VERSION 5.7 ;
  NOWIREEXTENSIONATPIN ON ;
  DIVIDERCHAR "/" ;
  BUSBITCHARS "[]" ;
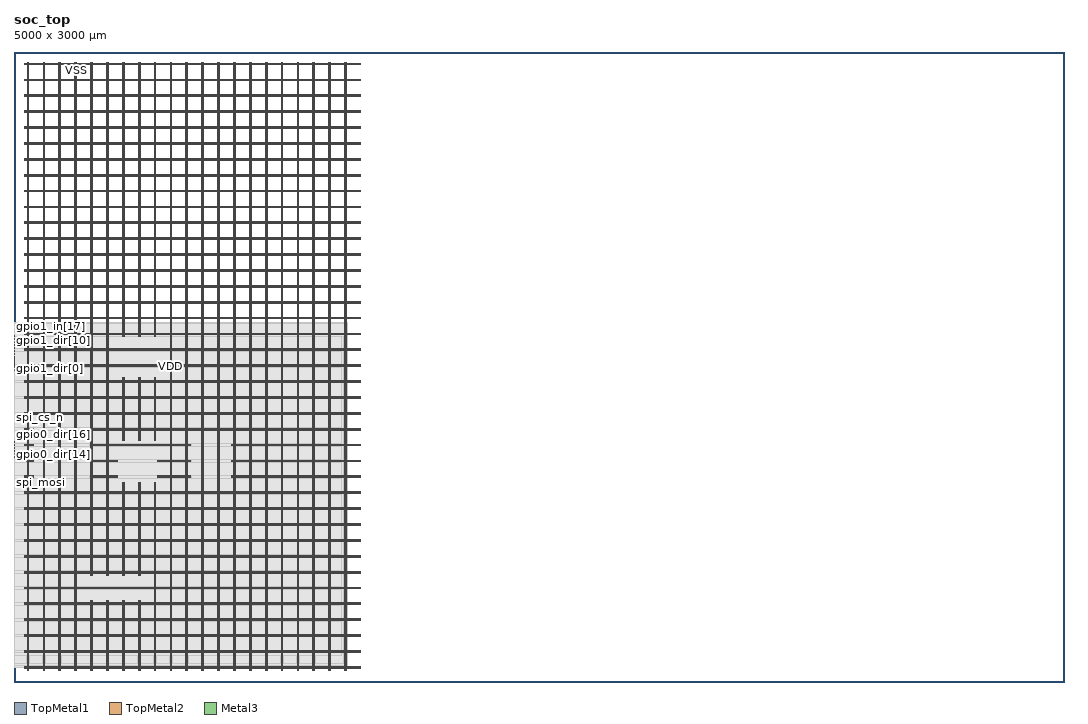
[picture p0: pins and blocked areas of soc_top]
MACRO soc_top
  CLASS BLOCK ;
  FOREIGN soc_top ;
  ORIGIN 0.000 0.000 ;
  SIZE 5000.000 BY 3000.000 ;
  PIN VDD
    DIRECTION INOUT ;
    USE POWER ;
    PORT
      LAYER TopMetal1 ;
        RECT 62.900 52.920 65.100 2948.400 ;
    END
    PORT
      LAYER TopMetal1 ;
        RECT 138.500 52.920 140.700 2948.400 ;
    END
    PORT
      LAYER TopMetal1 ;
        RECT 214.100 52.920 216.300 2948.400 ;
    END
    PORT
      LAYER TopMetal1 ;
        RECT 289.700 52.920 291.900 2948.400 ;
    END
    PORT
      LAYER TopMetal1 ;
        RECT 365.300 52.920 367.500 389.940 ;
    END
    PORT
      LAYER TopMetal1 ;
        RECT 365.300 508.100 367.500 2948.400 ;
    END
    PORT
      LAYER TopMetal1 ;
        RECT 440.900 52.920 443.100 389.940 ;
    END
    PORT
      LAYER TopMetal1 ;
        RECT 440.900 508.100 443.100 2948.400 ;
    END
    PORT
      LAYER TopMetal1 ;
        RECT 516.500 52.920 518.700 389.940 ;
    END
    PORT
      LAYER TopMetal1 ;
        RECT 516.500 508.100 518.700 951.620 ;
    END
    PORT
      LAYER TopMetal1 ;
        RECT 516.500 1151.880 518.700 1451.620 ;
    END
    PORT
      LAYER TopMetal1 ;
        RECT 516.500 1644.940 518.700 2948.400 ;
    END
    PORT
      LAYER TopMetal1 ;
        RECT 592.100 52.920 594.300 389.940 ;
    END
    PORT
      LAYER TopMetal1 ;
        RECT 592.100 508.100 594.300 951.620 ;
    END
    PORT
      LAYER TopMetal1 ;
        RECT 592.100 1151.880 594.300 1451.620 ;
    END
    PORT
      LAYER TopMetal1 ;
        RECT 592.100 1644.940 594.300 2948.400 ;
    END
    PORT
      LAYER TopMetal1 ;
        RECT 667.700 52.920 669.900 951.620 ;
    END
    PORT
      LAYER TopMetal1 ;
        RECT 667.700 1151.880 669.900 1451.620 ;
    END
    PORT
      LAYER TopMetal1 ;
        RECT 667.700 1644.940 669.900 2948.400 ;
    END
    PORT
      LAYER TopMetal1 ;
        RECT 743.300 52.920 745.500 2948.400 ;
    END
    PORT
      LAYER TopMetal1 ;
        RECT 818.900 52.920 821.100 2948.400 ;
    END
    PORT
      LAYER TopMetal1 ;
        RECT 894.500 52.920 896.700 2948.400 ;
    END
    PORT
      LAYER TopMetal1 ;
        RECT 970.100 52.920 972.300 2948.400 ;
    END
    PORT
      LAYER TopMetal1 ;
        RECT 1045.700 52.920 1047.900 2948.400 ;
    END
    PORT
      LAYER TopMetal1 ;
        RECT 1121.300 52.920 1123.500 2948.400 ;
    END
    PORT
      LAYER TopMetal1 ;
        RECT 1196.900 52.920 1199.100 2948.400 ;
    END
    PORT
      LAYER TopMetal1 ;
        RECT 1272.500 52.920 1274.700 2948.400 ;
    END
    PORT
      LAYER TopMetal1 ;
        RECT 1348.100 52.920 1350.300 2948.400 ;
    END
    PORT
      LAYER TopMetal1 ;
        RECT 1423.700 52.920 1425.900 2948.400 ;
    END
    PORT
      LAYER TopMetal1 ;
        RECT 1499.300 52.920 1501.500 2948.400 ;
    END
    PORT
      LAYER TopMetal1 ;
        RECT 1574.900 52.920 1577.100 2948.400 ;
    END
    PORT
      LAYER TopMetal2 ;
        RECT 50.400 65.420 1649.760 67.620 ;
    END
    PORT
      LAYER TopMetal2 ;
        RECT 50.400 141.020 1649.760 143.220 ;
    END
    PORT
      LAYER TopMetal2 ;
        RECT 50.400 216.620 1649.760 218.820 ;
    END
    PORT
      LAYER TopMetal2 ;
        RECT 50.400 292.220 1649.760 294.420 ;
    END
    PORT
      LAYER TopMetal2 ;
        RECT 50.400 367.820 1649.760 370.020 ;
    END
    PORT
      LAYER TopMetal2 ;
        RECT 50.400 443.420 1649.760 445.620 ;
    END
    PORT
      LAYER TopMetal2 ;
        RECT 50.400 519.020 1649.760 521.220 ;
    END
    PORT
      LAYER TopMetal2 ;
        RECT 50.400 594.620 1649.760 596.820 ;
    END
    PORT
      LAYER TopMetal2 ;
        RECT 50.400 670.220 1649.760 672.420 ;
    END
    PORT
      LAYER TopMetal2 ;
        RECT 50.400 745.820 1649.760 748.020 ;
    END
    PORT
      LAYER TopMetal2 ;
        RECT 50.400 821.420 1649.760 823.620 ;
    END
    PORT
      LAYER TopMetal2 ;
        RECT 50.400 897.020 1649.760 899.220 ;
    END
    PORT
      LAYER TopMetal2 ;
        RECT 50.400 972.620 91.760 974.820 ;
    END
    PORT
      LAYER TopMetal2 ;
        RECT 50.400 1048.220 91.760 1050.420 ;
    END
    PORT
      LAYER TopMetal2 ;
        RECT 50.400 1123.820 91.760 1126.020 ;
    END
    PORT
      LAYER TopMetal2 ;
        RECT 50.400 1199.420 91.760 1201.620 ;
    END
    PORT
      LAYER TopMetal2 ;
        RECT 50.400 1275.020 1649.760 1277.220 ;
    END
    PORT
      LAYER TopMetal2 ;
        RECT 50.400 1350.620 1649.760 1352.820 ;
    END
    PORT
      LAYER TopMetal2 ;
        RECT 50.400 1426.220 1649.760 1428.420 ;
    END
    PORT
      LAYER TopMetal2 ;
        RECT 50.400 1501.820 1649.760 1504.020 ;
    END
    PORT
      LAYER TopMetal2 ;
        RECT 50.400 1577.420 1649.760 1579.620 ;
    END
    PORT
      LAYER TopMetal2 ;
        RECT 50.400 1653.020 1649.760 1655.220 ;
    END
    PORT
      LAYER TopMetal2 ;
        RECT 50.400 1728.620 1649.760 1730.820 ;
    END
    PORT
      LAYER TopMetal2 ;
        RECT 50.400 1804.220 1649.760 1806.420 ;
    END
    PORT
      LAYER TopMetal2 ;
        RECT 50.400 1879.820 1649.760 1882.020 ;
    END
    PORT
      LAYER TopMetal2 ;
        RECT 50.400 1955.420 1649.760 1957.620 ;
    END
    PORT
      LAYER TopMetal2 ;
        RECT 50.400 2031.020 1649.760 2033.220 ;
    END
    PORT
      LAYER TopMetal2 ;
        RECT 50.400 2106.620 1649.760 2108.820 ;
    END
    PORT
      LAYER TopMetal2 ;
        RECT 50.400 2182.220 1649.760 2184.420 ;
    END
    PORT
      LAYER TopMetal2 ;
        RECT 50.400 2257.820 1649.760 2260.020 ;
    END
    PORT
      LAYER TopMetal2 ;
        RECT 50.400 2333.420 1649.760 2335.620 ;
    END
    PORT
      LAYER TopMetal2 ;
        RECT 50.400 2409.020 1649.760 2411.220 ;
    END
    PORT
      LAYER TopMetal2 ;
        RECT 50.400 2484.620 1649.760 2486.820 ;
    END
    PORT
      LAYER TopMetal2 ;
        RECT 50.400 2560.220 1649.760 2562.420 ;
    END
    PORT
      LAYER TopMetal2 ;
        RECT 50.400 2635.820 1649.760 2638.020 ;
    END
    PORT
      LAYER TopMetal2 ;
        RECT 50.400 2711.420 1649.760 2713.620 ;
    END
    PORT
      LAYER TopMetal2 ;
        RECT 50.400 2787.020 1649.760 2789.220 ;
    END
    PORT
      LAYER TopMetal2 ;
        RECT 50.400 2862.620 1649.760 2864.820 ;
    END
    PORT
      LAYER TopMetal2 ;
        RECT 50.400 2938.220 1649.760 2940.420 ;
    END
    PORT
      LAYER TopMetal2 ;
        RECT 362.640 972.620 491.760 974.820 ;
    END
    PORT
      LAYER TopMetal2 ;
        RECT 362.640 1048.220 491.760 1050.420 ;
    END
    PORT
      LAYER TopMetal2 ;
        RECT 362.640 1123.820 841.760 1126.020 ;
    END
    PORT
      LAYER TopMetal2 ;
        RECT 362.640 1199.420 1649.760 1201.620 ;
    END
    PORT
      LAYER TopMetal2 ;
        RECT 685.660 972.620 841.760 974.820 ;
    END
    PORT
      LAYER TopMetal2 ;
        RECT 685.660 1048.220 841.760 1050.420 ;
    END
    PORT
      LAYER TopMetal2 ;
        RECT 1036.320 972.620 1649.760 974.820 ;
    END
    PORT
      LAYER TopMetal2 ;
        RECT 1036.320 1048.220 1649.760 1050.420 ;
    END
    PORT
      LAYER TopMetal2 ;
        RECT 1036.320 1123.820 1649.760 1126.020 ;
    END
  END VDD
  PIN VSS
    DIRECTION INOUT ;
    USE GROUND ;
    PORT
      LAYER TopMetal1 ;
        RECT 69.100 52.920 71.300 2948.400 ;
    END
    PORT
      LAYER TopMetal1 ;
        RECT 144.700 52.920 146.900 2948.400 ;
    END
    PORT
      LAYER TopMetal1 ;
        RECT 220.300 52.920 222.500 2948.400 ;
    END
    PORT
      LAYER TopMetal1 ;
        RECT 295.900 52.920 298.100 2948.400 ;
    END
    PORT
      LAYER TopMetal1 ;
        RECT 371.500 52.920 373.700 389.940 ;
    END
    PORT
      LAYER TopMetal1 ;
        RECT 371.500 508.100 373.700 2948.400 ;
    END
    PORT
      LAYER TopMetal1 ;
        RECT 447.100 52.920 449.300 389.940 ;
    END
    PORT
      LAYER TopMetal1 ;
        RECT 447.100 508.100 449.300 2948.400 ;
    END
    PORT
      LAYER TopMetal1 ;
        RECT 522.700 52.920 524.900 389.940 ;
    END
    PORT
      LAYER TopMetal1 ;
        RECT 522.700 508.100 524.900 951.210 ;
    END
    PORT
      LAYER TopMetal1 ;
        RECT 522.700 1151.880 524.900 1451.210 ;
    END
    PORT
      LAYER TopMetal1 ;
        RECT 522.700 1645.350 524.900 2948.400 ;
    END
    PORT
      LAYER TopMetal1 ;
        RECT 598.300 52.920 600.500 389.940 ;
    END
    PORT
      LAYER TopMetal1 ;
        RECT 598.300 508.100 600.500 951.210 ;
    END
    PORT
      LAYER TopMetal1 ;
        RECT 598.300 1151.880 600.500 1451.210 ;
    END
    PORT
      LAYER TopMetal1 ;
        RECT 598.300 1645.350 600.500 2948.400 ;
    END
    PORT
      LAYER TopMetal1 ;
        RECT 673.900 52.920 676.100 951.620 ;
    END
    PORT
      LAYER TopMetal1 ;
        RECT 673.900 1151.880 676.100 1451.620 ;
    END
    PORT
      LAYER TopMetal1 ;
        RECT 673.900 1644.940 676.100 2948.400 ;
    END
    PORT
      LAYER TopMetal1 ;
        RECT 749.500 52.920 751.700 2948.400 ;
    END
    PORT
      LAYER TopMetal1 ;
        RECT 825.100 52.920 827.300 2948.400 ;
    END
    PORT
      LAYER TopMetal1 ;
        RECT 900.700 52.920 902.900 2948.400 ;
    END
    PORT
      LAYER TopMetal1 ;
        RECT 976.300 52.920 978.500 2948.400 ;
    END
    PORT
      LAYER TopMetal1 ;
        RECT 1051.900 52.920 1054.100 2948.400 ;
    END
    PORT
      LAYER TopMetal1 ;
        RECT 1127.500 52.920 1129.700 2948.400 ;
    END
    PORT
      LAYER TopMetal1 ;
        RECT 1203.100 52.920 1205.300 2948.400 ;
    END
    PORT
      LAYER TopMetal1 ;
        RECT 1278.700 52.920 1280.900 2948.400 ;
    END
    PORT
      LAYER TopMetal1 ;
        RECT 1354.300 52.920 1356.500 2948.400 ;
    END
    PORT
      LAYER TopMetal1 ;
        RECT 1429.900 52.920 1432.100 2948.400 ;
    END
    PORT
      LAYER TopMetal1 ;
        RECT 1505.500 52.920 1507.700 2948.400 ;
    END
    PORT
      LAYER TopMetal1 ;
        RECT 1581.100 52.920 1583.300 2948.400 ;
    END
    PORT
      LAYER TopMetal2 ;
        RECT 50.400 71.620 1649.760 73.820 ;
    END
    PORT
      LAYER TopMetal2 ;
        RECT 50.400 147.220 1649.760 149.420 ;
    END
    PORT
      LAYER TopMetal2 ;
        RECT 50.400 222.820 1649.760 225.020 ;
    END
    PORT
      LAYER TopMetal2 ;
        RECT 50.400 298.420 1649.760 300.620 ;
    END
    PORT
      LAYER TopMetal2 ;
        RECT 50.400 374.020 1649.760 376.220 ;
    END
    PORT
      LAYER TopMetal2 ;
        RECT 50.400 449.620 1649.760 451.820 ;
    END
    PORT
      LAYER TopMetal2 ;
        RECT 50.400 525.220 1649.760 527.420 ;
    END
    PORT
      LAYER TopMetal2 ;
        RECT 50.400 600.820 1649.760 603.020 ;
    END
    PORT
      LAYER TopMetal2 ;
        RECT 50.400 676.420 1649.760 678.620 ;
    END
    PORT
      LAYER TopMetal2 ;
        RECT 50.400 752.020 1649.760 754.220 ;
    END
    PORT
      LAYER TopMetal2 ;
        RECT 50.400 827.620 1649.760 829.820 ;
    END
    PORT
      LAYER TopMetal2 ;
        RECT 50.400 903.220 1649.760 905.420 ;
    END
    PORT
      LAYER TopMetal2 ;
        RECT 50.400 978.820 91.760 981.020 ;
    END
    PORT
      LAYER TopMetal2 ;
        RECT 50.400 1054.420 91.760 1056.620 ;
    END
    PORT
      LAYER TopMetal2 ;
        RECT 50.400 1130.020 91.760 1132.220 ;
    END
    PORT
      LAYER TopMetal2 ;
        RECT 50.400 1205.620 91.760 1207.820 ;
    END
    PORT
      LAYER TopMetal2 ;
        RECT 50.400 1281.220 1649.760 1283.420 ;
    END
    PORT
      LAYER TopMetal2 ;
        RECT 50.400 1356.820 1649.760 1359.020 ;
    END
    PORT
      LAYER TopMetal2 ;
        RECT 50.400 1432.420 1649.760 1434.620 ;
    END
    PORT
      LAYER TopMetal2 ;
        RECT 50.400 1508.020 1649.760 1510.220 ;
    END
    PORT
      LAYER TopMetal2 ;
        RECT 50.400 1583.620 1649.760 1585.820 ;
    END
    PORT
      LAYER TopMetal2 ;
        RECT 50.400 1659.220 1649.760 1661.420 ;
    END
    PORT
      LAYER TopMetal2 ;
        RECT 50.400 1734.820 1649.760 1737.020 ;
    END
    PORT
      LAYER TopMetal2 ;
        RECT 50.400 1810.420 1649.760 1812.620 ;
    END
    PORT
      LAYER TopMetal2 ;
        RECT 50.400 1886.020 1649.760 1888.220 ;
    END
    PORT
      LAYER TopMetal2 ;
        RECT 50.400 1961.620 1649.760 1963.820 ;
    END
    PORT
      LAYER TopMetal2 ;
        RECT 50.400 2037.220 1649.760 2039.420 ;
    END
    PORT
      LAYER TopMetal2 ;
        RECT 50.400 2112.820 1649.760 2115.020 ;
    END
    PORT
      LAYER TopMetal2 ;
        RECT 50.400 2188.420 1649.760 2190.620 ;
    END
    PORT
      LAYER TopMetal2 ;
        RECT 50.400 2264.020 1649.760 2266.220 ;
    END
    PORT
      LAYER TopMetal2 ;
        RECT 50.400 2339.620 1649.760 2341.820 ;
    END
    PORT
      LAYER TopMetal2 ;
        RECT 50.400 2415.220 1649.760 2417.420 ;
    END
    PORT
      LAYER TopMetal2 ;
        RECT 50.400 2490.820 1649.760 2493.020 ;
    END
    PORT
      LAYER TopMetal2 ;
        RECT 50.400 2566.420 1649.760 2568.620 ;
    END
    PORT
      LAYER TopMetal2 ;
        RECT 50.400 2642.020 1649.760 2644.220 ;
    END
    PORT
      LAYER TopMetal2 ;
        RECT 50.400 2717.620 1649.760 2719.820 ;
    END
    PORT
      LAYER TopMetal2 ;
        RECT 50.400 2793.220 1649.760 2795.420 ;
    END
    PORT
      LAYER TopMetal2 ;
        RECT 50.400 2868.820 1649.760 2871.020 ;
    END
    PORT
      LAYER TopMetal2 ;
        RECT 50.400 2944.420 1649.760 2946.620 ;
    END
    PORT
      LAYER TopMetal2 ;
        RECT 362.640 978.820 491.760 981.020 ;
    END
    PORT
      LAYER TopMetal2 ;
        RECT 362.640 1054.420 491.760 1056.620 ;
    END
    PORT
      LAYER TopMetal2 ;
        RECT 362.640 1130.020 841.760 1132.220 ;
    END
    PORT
      LAYER TopMetal2 ;
        RECT 362.640 1205.620 1649.760 1207.820 ;
    END
    PORT
      LAYER TopMetal2 ;
        RECT 685.660 978.820 841.760 981.020 ;
    END
    PORT
      LAYER TopMetal2 ;
        RECT 685.660 1054.420 841.760 1056.620 ;
    END
    PORT
      LAYER TopMetal2 ;
        RECT 1036.320 978.820 1649.760 981.020 ;
    END
    PORT
      LAYER TopMetal2 ;
        RECT 1036.320 1054.420 1649.760 1056.620 ;
    END
    PORT
      LAYER TopMetal2 ;
        RECT 1036.320 1130.020 1649.760 1132.220 ;
    END
  END VSS
  PIN clk_i
    DIRECTION INPUT ;
    USE SIGNAL ;
    ANTENNAGATEAREA 1.450800 ;
    PORT
      LAYER Metal3 ;
        RECT 0.000 1485.340 0.400 1485.740 ;
    END
  END clk_i
  PIN gpio0_dir[0]
    DIRECTION OUTPUT ;
    USE SIGNAL ;
    ANTENNADIFFAREA 0.708600 ;
    PORT
      LAYER Metal3 ;
        RECT 0.000 1069.540 0.400 1069.940 ;
    END
  END gpio0_dir[0]
  PIN gpio0_dir[10]
    DIRECTION OUTPUT ;
    USE SIGNAL ;
    ANTENNADIFFAREA 0.708600 ;
    PORT
      LAYER Metal3 ;
        RECT 0.000 1142.620 0.400 1143.020 ;
    END
  END gpio0_dir[10]
  PIN gpio0_dir[11]
    DIRECTION OUTPUT ;
    USE SIGNAL ;
    ANTENNADIFFAREA 0.708600 ;
    PORT
      LAYER Metal3 ;
        RECT 0.000 1109.020 0.400 1109.420 ;
    END
  END gpio0_dir[11]
  PIN gpio0_dir[12]
    DIRECTION OUTPUT ;
    USE SIGNAL ;
    ANTENNADIFFAREA 0.708600 ;
    PORT
      LAYER Metal3 ;
        RECT 0.000 1124.980 0.400 1125.380 ;
    END
  END gpio0_dir[12]
  PIN gpio0_dir[13]
    DIRECTION OUTPUT ;
    USE SIGNAL ;
    ANTENNADIFFAREA 0.708600 ;
    PORT
      LAYER Metal3 ;
        RECT 0.000 1130.860 0.400 1131.260 ;
    END
  END gpio0_dir[13]
  PIN gpio0_dir[14]
    DIRECTION OUTPUT ;
    USE SIGNAL ;
    ANTENNADIFFAREA 0.708600 ;
    PORT
      LAYER Metal3 ;
        RECT 0.000 1084.660 0.400 1085.060 ;
    END
  END gpio0_dir[14]
  PIN gpio0_dir[15]
    DIRECTION OUTPUT ;
    USE SIGNAL ;
    ANTENNADIFFAREA 0.708600 ;
    PORT
      LAYER Metal3 ;
        RECT 0.000 1137.580 0.400 1137.980 ;
    END
  END gpio0_dir[15]
  PIN gpio0_dir[16]
    DIRECTION OUTPUT ;
    USE SIGNAL ;
    ANTENNADIFFAREA 0.708600 ;
    PORT
      LAYER Metal3 ;
        RECT 0.000 1138.420 0.400 1138.820 ;
    END
  END gpio0_dir[16]
  PIN gpio0_dir[17]
    DIRECTION OUTPUT ;
    USE SIGNAL ;
    ANTENNADIFFAREA 0.708600 ;
    PORT
      LAYER Metal3 ;
        RECT 0.000 1098.940 0.400 1099.340 ;
    END
  END gpio0_dir[17]
  PIN gpio0_dir[18]
    DIRECTION OUTPUT ;
    USE SIGNAL ;
    ANTENNADIFFAREA 0.708600 ;
    PORT
      LAYER Metal3 ;
        RECT 0.000 1083.820 0.400 1084.220 ;
    END
  END gpio0_dir[18]
  PIN gpio0_dir[19]
    DIRECTION OUTPUT ;
    USE SIGNAL ;
    ANTENNADIFFAREA 0.708600 ;
    PORT
      LAYER Metal3 ;
        RECT 0.000 1139.260 0.400 1139.660 ;
    END
  END gpio0_dir[19]
  PIN gpio0_dir[1]
    DIRECTION OUTPUT ;
    USE SIGNAL ;
    ANTENNADIFFAREA 0.708600 ;
    PORT
      LAYER Metal3 ;
        RECT 0.000 1106.500 0.400 1106.900 ;
    END
  END gpio0_dir[1]
  PIN gpio0_dir[20]
    DIRECTION OUTPUT ;
    USE SIGNAL ;
    ANTENNADIFFAREA 0.708600 ;
    PORT
      LAYER Metal3 ;
        RECT 0.000 1134.220 0.400 1134.620 ;
    END
  END gpio0_dir[20]
  PIN gpio0_dir[21]
    DIRECTION OUTPUT ;
    USE SIGNAL ;
    ANTENNADIFFAREA 0.708600 ;
    PORT
      LAYER Metal3 ;
        RECT 0.000 1082.980 0.400 1083.380 ;
    END
  END gpio0_dir[21]
  PIN gpio0_dir[22]
    DIRECTION OUTPUT ;
    USE SIGNAL ;
    ANTENNADIFFAREA 0.708600 ;
    PORT
      LAYER Metal3 ;
        RECT 0.000 1105.660 0.400 1106.060 ;
    END
  END gpio0_dir[22]
  PIN gpio0_dir[23]
    DIRECTION OUTPUT ;
    USE SIGNAL ;
    ANTENNADIFFAREA 0.708600 ;
    PORT
      LAYER Metal3 ;
        RECT 0.000 1121.620 0.400 1122.020 ;
    END
  END gpio0_dir[23]
  PIN gpio0_dir[24]
    DIRECTION OUTPUT ;
    USE SIGNAL ;
    ANTENNADIFFAREA 0.708600 ;
    PORT
      LAYER Metal3 ;
        RECT 0.000 1148.500 0.400 1148.900 ;
    END
  END gpio0_dir[24]
  PIN gpio0_dir[25]
    DIRECTION OUTPUT ;
    USE SIGNAL ;
    ANTENNADIFFAREA 0.708600 ;
    PORT
      LAYER Metal3 ;
        RECT 0.000 1082.140 0.400 1082.540 ;
    END
  END gpio0_dir[25]
  PIN gpio0_dir[26]
    DIRECTION OUTPUT ;
    USE SIGNAL ;
    ANTENNADIFFAREA 0.708600 ;
    PORT
      LAYER Metal3 ;
        RECT 0.000 1074.580 0.400 1074.980 ;
    END
  END gpio0_dir[26]
  PIN gpio0_dir[27]
    DIRECTION OUTPUT ;
    USE SIGNAL ;
    ANTENNADIFFAREA 0.708600 ;
    PORT
      LAYER Metal3 ;
        RECT 0.000 1141.780 0.400 1142.180 ;
    END
  END gpio0_dir[27]
  PIN gpio0_dir[28]
    DIRECTION OUTPUT ;
    USE SIGNAL ;
    ANTENNADIFFAREA 0.708600 ;
    PORT
      LAYER Metal3 ;
        RECT 0.000 1103.980 0.400 1104.380 ;
    END
  END gpio0_dir[28]
  PIN gpio0_dir[29]
    DIRECTION OUTPUT ;
    USE SIGNAL ;
    ANTENNADIFFAREA 0.708600 ;
    PORT
      LAYER Metal3 ;
        RECT 0.000 1119.940 0.400 1120.340 ;
    END
  END gpio0_dir[29]
  PIN gpio0_dir[2]
    DIRECTION OUTPUT ;
    USE SIGNAL ;
    ANTENNADIFFAREA 0.708600 ;
    PORT
      LAYER Metal3 ;
        RECT 0.000 1081.300 0.400 1081.700 ;
    END
  END gpio0_dir[2]
  PIN gpio0_dir[30]
    DIRECTION OUTPUT ;
    USE SIGNAL ;
    ANTENNADIFFAREA 0.708600 ;
    PORT
      LAYER Metal3 ;
        RECT 0.000 1103.140 0.400 1103.540 ;
    END
  END gpio0_dir[30]
  PIN gpio0_dir[31]
    DIRECTION OUTPUT ;
    USE SIGNAL ;
    ANTENNADIFFAREA 0.708600 ;
    PORT
      LAYER Metal3 ;
        RECT 0.000 1144.300 0.400 1144.700 ;
    END
  END gpio0_dir[31]
  PIN gpio0_dir[3]
    DIRECTION OUTPUT ;
    USE SIGNAL ;
    ANTENNADIFFAREA 0.708600 ;
    PORT
      LAYER Metal3 ;
        RECT 0.000 1111.540 0.400 1111.940 ;
    END
  END gpio0_dir[3]
  PIN gpio0_dir[4]
    DIRECTION OUTPUT ;
    USE SIGNAL ;
    ANTENNADIFFAREA 0.708600 ;
    PORT
      LAYER Metal3 ;
        RECT 0.000 1079.620 0.400 1080.020 ;
    END
  END gpio0_dir[4]
  PIN gpio0_dir[5]
    DIRECTION OUTPUT ;
    USE SIGNAL ;
    ANTENNADIFFAREA 0.708600 ;
    PORT
      LAYER Metal3 ;
        RECT 0.000 1080.460 0.400 1080.860 ;
    END
  END gpio0_dir[5]
  PIN gpio0_dir[6]
    DIRECTION OUTPUT ;
    USE SIGNAL ;
    ANTENNADIFFAREA 0.708600 ;
    PORT
      LAYER Metal3 ;
        RECT 0.000 1112.380 0.400 1112.780 ;
    END
  END gpio0_dir[6]
  PIN gpio0_dir[7]
    DIRECTION OUTPUT ;
    USE SIGNAL ;
    ANTENNADIFFAREA 0.708600 ;
    PORT
      LAYER Metal3 ;
        RECT 0.000 1071.220 0.400 1071.620 ;
    END
  END gpio0_dir[7]
  PIN gpio0_dir[8]
    DIRECTION OUTPUT ;
    USE SIGNAL ;
    ANTENNADIFFAREA 0.708600 ;
    PORT
      LAYER Metal3 ;
        RECT 0.000 1133.380 0.400 1133.780 ;
    END
  END gpio0_dir[8]
  PIN gpio0_dir[9]
    DIRECTION OUTPUT ;
    USE SIGNAL ;
    ANTENNADIFFAREA 0.708600 ;
    PORT
      LAYER Metal3 ;
        RECT 0.000 1136.740 0.400 1137.140 ;
    END
  END gpio0_dir[9]
  PIN gpio0_in[0]
    DIRECTION INPUT ;
    USE SIGNAL ;
    ANTENNAGATEAREA 0.109200 ;
    ANTENNADIFFAREA 2.015400 ;
    PORT
      LAYER Metal3 ;
        RECT 0.000 1070.380 0.400 1070.780 ;
    END
  END gpio0_in[0]
  PIN gpio0_in[10]
    DIRECTION INPUT ;
    USE SIGNAL ;
    ANTENNAGATEAREA 0.109200 ;
    ANTENNADIFFAREA 4.030800 ;
    PORT
      LAYER Metal3 ;
        RECT 0.000 1073.740 0.400 1074.140 ;
    END
  END gpio0_in[10]
  PIN gpio0_in[11]
    DIRECTION INPUT ;
    USE SIGNAL ;
    ANTENNAGATEAREA 0.109200 ;
    ANTENNADIFFAREA 2.015400 ;
    PORT
      LAYER Metal3 ;
        RECT 0.000 1123.300 0.400 1123.700 ;
    END
  END gpio0_in[11]
  PIN gpio0_in[12]
    DIRECTION INPUT ;
    USE SIGNAL ;
    ANTENNAGATEAREA 0.109200 ;
    ANTENNADIFFAREA 2.015400 ;
    PORT
      LAYER Metal3 ;
        RECT 0.000 1099.780 0.400 1100.180 ;
    END
  END gpio0_in[12]
  PIN gpio0_in[13]
    DIRECTION INPUT ;
    USE SIGNAL ;
    ANTENNAGATEAREA 0.109200 ;
    ANTENNADIFFAREA 2.015400 ;
    PORT
      LAYER Metal3 ;
        RECT 0.000 1145.980 0.400 1146.380 ;
    END
  END gpio0_in[13]
  PIN gpio0_in[14]
    DIRECTION INPUT ;
    USE SIGNAL ;
    ANTENNAGATEAREA 0.109200 ;
    ANTENNADIFFAREA 2.015400 ;
    PORT
      LAYER Metal3 ;
        RECT 0.000 1125.820 0.400 1126.220 ;
    END
  END gpio0_in[14]
  PIN gpio0_in[15]
    DIRECTION INPUT ;
    USE SIGNAL ;
    ANTENNAGATEAREA 0.109200 ;
    ANTENNADIFFAREA 2.015400 ;
    PORT
      LAYER Metal3 ;
        RECT 0.000 1078.780 0.400 1079.180 ;
    END
  END gpio0_in[15]
  PIN gpio0_in[16]
    DIRECTION INPUT ;
    USE SIGNAL ;
    ANTENNAGATEAREA 0.109200 ;
    ANTENNADIFFAREA 2.015400 ;
    PORT
      LAYER Metal3 ;
        RECT 0.000 1114.900 0.400 1115.300 ;
    END
  END gpio0_in[16]
  PIN gpio0_in[17]
    DIRECTION INPUT ;
    USE SIGNAL ;
    ANTENNAGATEAREA 0.109200 ;
    ANTENNADIFFAREA 2.015400 ;
    PORT
      LAYER Metal3 ;
        RECT 0.000 1143.460 0.400 1143.860 ;
    END
  END gpio0_in[17]
  PIN gpio0_in[18]
    DIRECTION INPUT ;
    USE SIGNAL ;
    ANTENNAGATEAREA 0.109200 ;
    ANTENNADIFFAREA 2.015400 ;
    PORT
      LAYER Metal3 ;
        RECT 0.000 1098.100 0.400 1098.500 ;
    END
  END gpio0_in[18]
  PIN gpio0_in[19]
    DIRECTION INPUT ;
    USE SIGNAL ;
    ANTENNAGATEAREA 0.109200 ;
    ANTENNADIFFAREA 2.015400 ;
    PORT
      LAYER Metal3 ;
        RECT 0.000 1146.820 0.400 1147.220 ;
    END
  END gpio0_in[19]
  PIN gpio0_in[1]
    DIRECTION INPUT ;
    USE SIGNAL ;
    ANTENNAGATEAREA 0.109200 ;
    ANTENNADIFFAREA 6.046200 ;
    PORT
      LAYER Metal3 ;
        RECT 0.000 1131.700 0.400 1132.100 ;
    END
  END gpio0_in[1]
  PIN gpio0_in[20]
    DIRECTION INPUT ;
    USE SIGNAL ;
    ANTENNAGATEAREA 0.109200 ;
    ANTENNADIFFAREA 2.015400 ;
    PORT
      LAYER Metal3 ;
        RECT 0.000 1097.260 0.400 1097.660 ;
    END
  END gpio0_in[20]
  PIN gpio0_in[21]
    DIRECTION INPUT ;
    USE SIGNAL ;
    ANTENNAGATEAREA 0.109200 ;
    ANTENNADIFFAREA 2.015400 ;
    PORT
      LAYER Metal3 ;
        RECT 0.000 1113.220 0.400 1113.620 ;
    END
  END gpio0_in[21]
  PIN gpio0_in[22]
    DIRECTION INPUT ;
    USE SIGNAL ;
    ANTENNAGATEAREA 0.109200 ;
    ANTENNADIFFAREA 2.015400 ;
    PORT
      LAYER Metal3 ;
        RECT 0.000 1140.100 0.400 1140.500 ;
    END
  END gpio0_in[22]
  PIN gpio0_in[23]
    DIRECTION INPUT ;
    USE SIGNAL ;
    ANTENNAGATEAREA 0.109200 ;
    ANTENNADIFFAREA 2.015400 ;
    PORT
      LAYER Metal3 ;
        RECT 0.000 1096.420 0.400 1096.820 ;
    END
  END gpio0_in[23]
  PIN gpio0_in[24]
    DIRECTION INPUT ;
    USE SIGNAL ;
    ANTENNAGATEAREA 0.109200 ;
    ANTENNADIFFAREA 2.015400 ;
    PORT
      LAYER Metal3 ;
        RECT 0.000 1124.140 0.400 1124.540 ;
    END
  END gpio0_in[24]
  PIN gpio0_in[25]
    DIRECTION INPUT ;
    USE SIGNAL ;
    ANTENNAGATEAREA 0.109200 ;
    ANTENNADIFFAREA 2.015400 ;
    PORT
      LAYER Metal3 ;
        RECT 0.000 1129.180 0.400 1129.580 ;
    END
  END gpio0_in[25]
  PIN gpio0_in[26]
    DIRECTION INPUT ;
    USE SIGNAL ;
    ANTENNAGATEAREA 0.109200 ;
    ANTENNADIFFAREA 2.015400 ;
    PORT
      LAYER Metal3 ;
        RECT 0.000 1095.580 0.400 1095.980 ;
    END
  END gpio0_in[26]
  PIN gpio0_in[27]
    DIRECTION INPUT ;
    USE SIGNAL ;
    ANTENNAGATEAREA 0.109200 ;
    ANTENNADIFFAREA 2.015400 ;
    PORT
      LAYER Metal3 ;
        RECT 0.000 1128.340 0.400 1128.740 ;
    END
  END gpio0_in[27]
  PIN gpio0_in[28]
    DIRECTION INPUT ;
    USE SIGNAL ;
    ANTENNAGATEAREA 0.109200 ;
    ANTENNADIFFAREA 2.015400 ;
    PORT
      LAYER Metal3 ;
        RECT 0.000 1072.900 0.400 1073.300 ;
    END
  END gpio0_in[28]
  PIN gpio0_in[29]
    DIRECTION INPUT ;
    USE SIGNAL ;
    ANTENNAGATEAREA 0.109200 ;
    ANTENNADIFFAREA 2.015400 ;
    PORT
      LAYER Metal3 ;
        RECT 0.000 1094.740 0.400 1095.140 ;
    END
  END gpio0_in[29]
  PIN gpio0_in[2]
    DIRECTION INPUT ;
    USE SIGNAL ;
    ANTENNAGATEAREA 0.109200 ;
    ANTENNADIFFAREA 2.015400 ;
    PORT
      LAYER Metal3 ;
        RECT 0.000 1117.420 0.400 1117.820 ;
    END
  END gpio0_in[2]
  PIN gpio0_in[30]
    DIRECTION INPUT ;
    USE SIGNAL ;
    ANTENNAGATEAREA 0.109200 ;
    ANTENNADIFFAREA 2.015400 ;
    PORT
      LAYER Metal3 ;
        RECT 0.000 1126.660 0.400 1127.060 ;
    END
  END gpio0_in[30]
  PIN gpio0_in[31]
    DIRECTION INPUT ;
    USE SIGNAL ;
    ANTENNAGATEAREA 0.109200 ;
    ANTENNADIFFAREA 2.015400 ;
    PORT
      LAYER Metal3 ;
        RECT 0.000 1093.900 0.400 1094.300 ;
    END
  END gpio0_in[31]
  PIN gpio0_in[3]
    DIRECTION INPUT ;
    USE SIGNAL ;
    ANTENNAGATEAREA 0.109200 ;
    ANTENNADIFFAREA 2.015400 ;
    PORT
      LAYER Metal3 ;
        RECT 0.000 1109.860 0.400 1110.260 ;
    END
  END gpio0_in[3]
  PIN gpio0_in[4]
    DIRECTION INPUT ;
    USE SIGNAL ;
    ANTENNAGATEAREA 0.109200 ;
    ANTENNADIFFAREA 2.015400 ;
    PORT
      LAYER Metal3 ;
        RECT 0.000 1108.180 0.400 1108.580 ;
    END
  END gpio0_in[4]
  PIN gpio0_in[5]
    DIRECTION INPUT ;
    USE SIGNAL ;
    ANTENNAGATEAREA 0.109200 ;
    ANTENNADIFFAREA 2.015400 ;
    PORT
      LAYER Metal3 ;
        RECT 0.000 1093.060 0.400 1093.460 ;
    END
  END gpio0_in[5]
  PIN gpio0_in[6]
    DIRECTION INPUT ;
    USE SIGNAL ;
    ANTENNAGATEAREA 0.109200 ;
    ANTENNADIFFAREA 2.015400 ;
    PORT
      LAYER Metal3 ;
        RECT 0.000 1140.940 0.400 1141.340 ;
    END
  END gpio0_in[6]
  PIN gpio0_in[7]
    DIRECTION INPUT ;
    USE SIGNAL ;
    ANTENNAGATEAREA 0.109200 ;
    ANTENNADIFFAREA 2.015400 ;
    PORT
      LAYER Metal3 ;
        RECT 0.000 1118.260 0.400 1118.660 ;
    END
  END gpio0_in[7]
  PIN gpio0_in[8]
    DIRECTION INPUT ;
    USE SIGNAL ;
    ANTENNAGATEAREA 0.109200 ;
    ANTENNADIFFAREA 2.015400 ;
    PORT
      LAYER Metal3 ;
        RECT 0.000 1145.140 0.400 1145.540 ;
    END
  END gpio0_in[8]
  PIN gpio0_in[9]
    DIRECTION INPUT ;
    USE SIGNAL ;
    ANTENNAGATEAREA 0.109200 ;
    ANTENNADIFFAREA 2.015400 ;
    PORT
      LAYER Metal3 ;
        RECT 0.000 1092.220 0.400 1092.620 ;
    END
  END gpio0_in[9]
  PIN gpio0_out[0]
    DIRECTION OUTPUT ;
    USE SIGNAL ;
    ANTENNADIFFAREA 0.708600 ;
    PORT
      LAYER Metal3 ;
        RECT 0.000 1077.940 0.400 1078.340 ;
    END
  END gpio0_out[0]
  PIN gpio0_out[10]
    DIRECTION OUTPUT ;
    USE SIGNAL ;
    ANTENNADIFFAREA 0.708600 ;
    PORT
      LAYER Metal3 ;
        RECT 0.000 1122.460 0.400 1122.860 ;
    END
  END gpio0_out[10]
  PIN gpio0_out[11]
    DIRECTION OUTPUT ;
    USE SIGNAL ;
    ANTENNADIFFAREA 0.708600 ;
    PORT
      LAYER Metal3 ;
        RECT 0.000 1147.660 0.400 1148.060 ;
    END
  END gpio0_out[11]
  PIN gpio0_out[12]
    DIRECTION OUTPUT ;
    USE SIGNAL ;
    ANTENNADIFFAREA 0.708600 ;
    PORT
      LAYER Metal3 ;
        RECT 0.000 1091.380 0.400 1091.780 ;
    END
  END gpio0_out[12]
  PIN gpio0_out[13]
    DIRECTION OUTPUT ;
    USE SIGNAL ;
    ANTENNADIFFAREA 0.708600 ;
    PORT
      LAYER Metal3 ;
        RECT 0.000 1132.540 0.400 1132.940 ;
    END
  END gpio0_out[13]
  PIN gpio0_out[14]
    DIRECTION OUTPUT ;
    USE SIGNAL ;
    ANTENNADIFFAREA 0.708600 ;
    PORT
      LAYER Metal3 ;
        RECT 0.000 1120.780 0.400 1121.180 ;
    END
  END gpio0_out[14]
  PIN gpio0_out[15]
    DIRECTION OUTPUT ;
    USE SIGNAL ;
    ANTENNADIFFAREA 0.708600 ;
    PORT
      LAYER Metal3 ;
        RECT 0.000 1116.580 0.400 1116.980 ;
    END
  END gpio0_out[15]
  PIN gpio0_out[16]
    DIRECTION OUTPUT ;
    USE SIGNAL ;
    ANTENNADIFFAREA 0.708600 ;
    PORT
      LAYER Metal3 ;
        RECT 0.000 1090.540 0.400 1090.940 ;
    END
  END gpio0_out[16]
  PIN gpio0_out[17]
    DIRECTION OUTPUT ;
    USE SIGNAL ;
    ANTENNADIFFAREA 0.708600 ;
    PORT
      LAYER Metal3 ;
        RECT 0.000 1135.060 0.400 1135.460 ;
    END
  END gpio0_out[17]
  PIN gpio0_out[18]
    DIRECTION OUTPUT ;
    USE SIGNAL ;
    ANTENNADIFFAREA 0.708600 ;
    PORT
      LAYER Metal3 ;
        RECT 0.000 1119.100 0.400 1119.500 ;
    END
  END gpio0_out[18]
  PIN gpio0_out[19]
    DIRECTION OUTPUT ;
    USE SIGNAL ;
    ANTENNADIFFAREA 0.708600 ;
    PORT
      LAYER Metal3 ;
        RECT 0.000 1077.100 0.400 1077.500 ;
    END
  END gpio0_out[19]
  PIN gpio0_out[1]
    DIRECTION OUTPUT ;
    USE SIGNAL ;
    ANTENNADIFFAREA 0.708600 ;
    PORT
      LAYER Metal3 ;
        RECT 0.000 1089.700 0.400 1090.100 ;
    END
  END gpio0_out[1]
  PIN gpio0_out[20]
    DIRECTION OUTPUT ;
    USE SIGNAL ;
    ANTENNADIFFAREA 0.708600 ;
    PORT
      LAYER Metal3 ;
        RECT 0.000 1101.460 0.400 1101.860 ;
    END
  END gpio0_out[20]
  PIN gpio0_out[21]
    DIRECTION OUTPUT ;
    USE SIGNAL ;
    ANTENNADIFFAREA 0.708600 ;
    PORT
      LAYER Metal3 ;
        RECT 0.000 1104.820 0.400 1105.220 ;
    END
  END gpio0_out[21]
  PIN gpio0_out[22]
    DIRECTION OUTPUT ;
    USE SIGNAL ;
    ANTENNADIFFAREA 0.708600 ;
    PORT
      LAYER Metal3 ;
        RECT 0.000 1100.620 0.400 1101.020 ;
    END
  END gpio0_out[22]
  PIN gpio0_out[23]
    DIRECTION OUTPUT ;
    USE SIGNAL ;
    ANTENNADIFFAREA 0.708600 ;
    PORT
      LAYER Metal3 ;
        RECT 0.000 1088.860 0.400 1089.260 ;
    END
  END gpio0_out[23]
  PIN gpio0_out[24]
    DIRECTION OUTPUT ;
    USE SIGNAL ;
    ANTENNADIFFAREA 0.708600 ;
    PORT
      LAYER Metal3 ;
        RECT 0.000 1135.900 0.400 1136.300 ;
    END
  END gpio0_out[24]
  PIN gpio0_out[25]
    DIRECTION OUTPUT ;
    USE SIGNAL ;
    ANTENNADIFFAREA 0.708600 ;
    PORT
      LAYER Metal3 ;
        RECT 0.000 1115.740 0.400 1116.140 ;
    END
  END gpio0_out[25]
  PIN gpio0_out[26]
    DIRECTION OUTPUT ;
    USE SIGNAL ;
    ANTENNADIFFAREA 0.708600 ;
    PORT
      LAYER Metal3 ;
        RECT 0.000 1076.260 0.400 1076.660 ;
    END
  END gpio0_out[26]
  PIN gpio0_out[27]
    DIRECTION OUTPUT ;
    USE SIGNAL ;
    ANTENNADIFFAREA 0.708600 ;
    PORT
      LAYER Metal3 ;
        RECT 0.000 1088.020 0.400 1088.420 ;
    END
  END gpio0_out[27]
  PIN gpio0_out[28]
    DIRECTION OUTPUT ;
    USE SIGNAL ;
    ANTENNADIFFAREA 0.708600 ;
    PORT
      LAYER Metal3 ;
        RECT 0.000 1102.300 0.400 1102.700 ;
    END
  END gpio0_out[28]
  PIN gpio0_out[29]
    DIRECTION OUTPUT ;
    USE SIGNAL ;
    ANTENNADIFFAREA 0.708600 ;
    PORT
      LAYER Metal3 ;
        RECT 0.000 1114.060 0.400 1114.460 ;
    END
  END gpio0_out[29]
  PIN gpio0_out[2]
    DIRECTION OUTPUT ;
    USE SIGNAL ;
    ANTENNADIFFAREA 0.708600 ;
    PORT
      LAYER Metal3 ;
        RECT 0.000 1149.340 0.400 1149.740 ;
    END
  END gpio0_out[2]
  PIN gpio0_out[30]
    DIRECTION OUTPUT ;
    USE SIGNAL ;
    ANTENNADIFFAREA 0.708600 ;
    PORT
      LAYER Metal3 ;
        RECT 0.000 1087.180 0.400 1087.580 ;
    END
  END gpio0_out[30]
  PIN gpio0_out[31]
    DIRECTION OUTPUT ;
    USE SIGNAL ;
    ANTENNADIFFAREA 0.708600 ;
    PORT
      LAYER Metal3 ;
        RECT 0.000 1127.500 0.400 1127.900 ;
    END
  END gpio0_out[31]
  PIN gpio0_out[3]
    DIRECTION OUTPUT ;
    USE SIGNAL ;
    ANTENNADIFFAREA 0.708600 ;
    PORT
      LAYER Metal3 ;
        RECT 0.000 1075.420 0.400 1075.820 ;
    END
  END gpio0_out[3]
  PIN gpio0_out[4]
    DIRECTION OUTPUT ;
    USE SIGNAL ;
    ANTENNADIFFAREA 0.708600 ;
    PORT
      LAYER Metal3 ;
        RECT 0.000 1107.340 0.400 1107.740 ;
    END
  END gpio0_out[4]
  PIN gpio0_out[5]
    DIRECTION OUTPUT ;
    USE SIGNAL ;
    ANTENNADIFFAREA 0.708600 ;
    PORT
      LAYER Metal3 ;
        RECT 0.000 1072.060 0.400 1072.460 ;
    END
  END gpio0_out[5]
  PIN gpio0_out[6]
    DIRECTION OUTPUT ;
    USE SIGNAL ;
    ANTENNADIFFAREA 0.708600 ;
    PORT
      LAYER Metal3 ;
        RECT 0.000 1086.340 0.400 1086.740 ;
    END
  END gpio0_out[6]
  PIN gpio0_out[7]
    DIRECTION OUTPUT ;
    USE SIGNAL ;
    ANTENNADIFFAREA 0.708600 ;
    PORT
      LAYER Metal3 ;
        RECT 0.000 1110.700 0.400 1111.100 ;
    END
  END gpio0_out[7]
  PIN gpio0_out[8]
    DIRECTION OUTPUT ;
    USE SIGNAL ;
    ANTENNADIFFAREA 0.708600 ;
    PORT
      LAYER Metal3 ;
        RECT 0.000 1130.020 0.400 1130.420 ;
    END
  END gpio0_out[8]
  PIN gpio0_out[9]
    DIRECTION OUTPUT ;
    USE SIGNAL ;
    ANTENNADIFFAREA 0.708600 ;
    PORT
      LAYER Metal3 ;
        RECT 0.000 1085.500 0.400 1085.900 ;
    END
  END gpio0_out[9]
  PIN gpio1_dir[0]
    DIRECTION OUTPUT ;
    USE SIGNAL ;
    ANTENNADIFFAREA 0.708600 ;
    PORT
      LAYER Metal3 ;
        RECT 0.000 1492.900 0.400 1493.300 ;
    END
  END gpio1_dir[0]
  PIN gpio1_dir[10]
    DIRECTION OUTPUT ;
    USE SIGNAL ;
    ANTENNADIFFAREA 0.708600 ;
    PORT
      LAYER Metal3 ;
        RECT 0.000 1623.940 0.400 1624.340 ;
    END
  END gpio1_dir[10]
  PIN gpio1_dir[11]
    DIRECTION OUTPUT ;
    USE SIGNAL ;
    ANTENNADIFFAREA 0.708600 ;
    PORT
      LAYER Metal3 ;
        RECT 0.000 1572.700 0.400 1573.100 ;
    END
  END gpio1_dir[11]
  PIN gpio1_dir[12]
    DIRECTION OUTPUT ;
    USE SIGNAL ;
    ANTENNADIFFAREA 0.708600 ;
    PORT
      LAYER Metal3 ;
        RECT 0.000 1642.420 0.400 1642.820 ;
    END
  END gpio1_dir[12]
  PIN gpio1_dir[13]
    DIRECTION OUTPUT ;
    USE SIGNAL ;
    ANTENNADIFFAREA 0.708600 ;
    PORT
      LAYER Metal3 ;
        RECT 0.000 1504.660 0.400 1505.060 ;
    END
  END gpio1_dir[13]
  PIN gpio1_dir[14]
    DIRECTION OUTPUT ;
    USE SIGNAL ;
    ANTENNADIFFAREA 0.708600 ;
    PORT
      LAYER Metal3 ;
        RECT 0.000 1571.860 0.400 1572.260 ;
    END
  END gpio1_dir[14]
  PIN gpio1_dir[15]
    DIRECTION OUTPUT ;
    USE SIGNAL ;
    ANTENNADIFFAREA 0.708600 ;
    PORT
      LAYER Metal3 ;
        RECT 0.000 1603.780 0.400 1604.180 ;
    END
  END gpio1_dir[15]
  PIN gpio1_dir[16]
    DIRECTION OUTPUT ;
    USE SIGNAL ;
    ANTENNADIFFAREA 0.708600 ;
    PORT
      LAYER Metal3 ;
        RECT 0.000 1639.900 0.400 1640.300 ;
    END
  END gpio1_dir[16]
  PIN gpio1_dir[17]
    DIRECTION OUTPUT ;
    USE SIGNAL ;
    ANTENNADIFFAREA 0.708600 ;
    PORT
      LAYER Metal3 ;
        RECT 0.000 1523.140 0.400 1523.540 ;
    END
  END gpio1_dir[17]
  PIN gpio1_dir[18]
    DIRECTION OUTPUT ;
    USE SIGNAL ;
    ANTENNADIFFAREA 0.708600 ;
    PORT
      LAYER Metal3 ;
        RECT 0.000 1649.980 0.400 1650.380 ;
    END
  END gpio1_dir[18]
  PIN gpio1_dir[19]
    DIRECTION OUTPUT ;
    USE SIGNAL ;
    ANTENNADIFFAREA 0.708600 ;
    PORT
      LAYER Metal3 ;
        RECT 0.000 1629.820 0.400 1630.220 ;
    END
  END gpio1_dir[19]
  PIN gpio1_dir[1]
    DIRECTION OUTPUT ;
    USE SIGNAL ;
    ANTENNADIFFAREA 0.708600 ;
    PORT
      LAYER Metal3 ;
        RECT 0.000 1497.100 0.400 1497.500 ;
    END
  END gpio1_dir[1]
  PIN gpio1_dir[20]
    DIRECTION OUTPUT ;
    USE SIGNAL ;
    ANTENNADIFFAREA 0.708600 ;
    PORT
      LAYER Metal3 ;
        RECT 0.000 1522.300 0.400 1522.700 ;
    END
  END gpio1_dir[20]
  PIN gpio1_dir[21]
    DIRECTION OUTPUT ;
    USE SIGNAL ;
    ANTENNADIFFAREA 0.708600 ;
    PORT
      LAYER Metal3 ;
        RECT 0.000 1552.540 0.400 1552.940 ;
    END
  END gpio1_dir[21]
  PIN gpio1_dir[22]
    DIRECTION OUTPUT ;
    USE SIGNAL ;
    ANTENNADIFFAREA 0.708600 ;
    PORT
      LAYER Metal3 ;
        RECT 0.000 1546.660 0.400 1547.060 ;
    END
  END gpio1_dir[22]
  PIN gpio1_dir[23]
    DIRECTION OUTPUT ;
    USE SIGNAL ;
    ANTENNADIFFAREA 0.708600 ;
    PORT
      LAYER Metal3 ;
        RECT 0.000 1634.020 0.400 1634.420 ;
    END
  END gpio1_dir[23]
  PIN gpio1_dir[24]
    DIRECTION OUTPUT ;
    USE SIGNAL ;
    ANTENNADIFFAREA 0.708600 ;
    PORT
      LAYER Metal3 ;
        RECT 0.000 1521.460 0.400 1521.860 ;
    END
  END gpio1_dir[24]
  PIN gpio1_dir[25]
    DIRECTION OUTPUT ;
    USE SIGNAL ;
    ANTENNADIFFAREA 0.708600 ;
    PORT
      LAYER Metal3 ;
        RECT 0.000 1568.500 0.400 1568.900 ;
    END
  END gpio1_dir[25]
  PIN gpio1_dir[26]
    DIRECTION OUTPUT ;
    USE SIGNAL ;
    ANTENNADIFFAREA 0.708600 ;
    PORT
      LAYER Metal3 ;
        RECT 0.000 1600.420 0.400 1600.820 ;
    END
  END gpio1_dir[26]
  PIN gpio1_dir[27]
    DIRECTION OUTPUT ;
    USE SIGNAL ;
    ANTENNADIFFAREA 0.708600 ;
    PORT
      LAYER Metal3 ;
        RECT 0.000 1640.740 0.400 1641.140 ;
    END
  END gpio1_dir[27]
  PIN gpio1_dir[28]
    DIRECTION OUTPUT ;
    USE SIGNAL ;
    ANTENNADIFFAREA 0.708600 ;
    PORT
      LAYER Metal3 ;
        RECT 0.000 1520.620 0.400 1521.020 ;
    END
  END gpio1_dir[28]
  PIN gpio1_dir[29]
    DIRECTION OUTPUT ;
    USE SIGNAL ;
    ANTENNADIFFAREA 0.708600 ;
    PORT
      LAYER Metal3 ;
        RECT 0.000 1631.500 0.400 1631.900 ;
    END
  END gpio1_dir[29]
  PIN gpio1_dir[2]
    DIRECTION OUTPUT ;
    USE SIGNAL ;
    ANTENNADIFFAREA 0.708600 ;
    PORT
      LAYER Metal3 ;
        RECT 0.000 1647.460 0.400 1647.860 ;
    END
  END gpio1_dir[2]
  PIN gpio1_dir[30]
    DIRECTION OUTPUT ;
    USE SIGNAL ;
    ANTENNADIFFAREA 0.708600 ;
    PORT
      LAYER Metal3 ;
        RECT 0.000 1566.820 0.400 1567.220 ;
    END
  END gpio1_dir[30]
  PIN gpio1_dir[31]
    DIRECTION OUTPUT ;
    USE SIGNAL ;
    ANTENNADIFFAREA 0.708600 ;
    PORT
      LAYER Metal3 ;
        RECT 0.000 1598.740 0.400 1599.140 ;
    END
  END gpio1_dir[31]
  PIN gpio1_dir[3]
    DIRECTION OUTPUT ;
    USE SIGNAL ;
    ANTENNADIFFAREA 0.708600 ;
    PORT
      LAYER Metal3 ;
        RECT 0.000 1519.780 0.400 1520.180 ;
    END
  END gpio1_dir[3]
  PIN gpio1_dir[4]
    DIRECTION OUTPUT ;
    USE SIGNAL ;
    ANTENNADIFFAREA 0.708600 ;
    PORT
      LAYER Metal3 ;
        RECT 0.000 1565.980 0.400 1566.380 ;
    END
  END gpio1_dir[4]
  PIN gpio1_dir[5]
    DIRECTION OUTPUT ;
    USE SIGNAL ;
    ANTENNADIFFAREA 0.708600 ;
    PORT
      LAYER Metal3 ;
        RECT 0.000 1639.060 0.400 1639.460 ;
    END
  END gpio1_dir[5]
  PIN gpio1_dir[6]
    DIRECTION OUTPUT ;
    USE SIGNAL ;
    ANTENNADIFFAREA 0.708600 ;
    PORT
      LAYER Metal3 ;
        RECT 0.000 1503.820 0.400 1504.220 ;
    END
  END gpio1_dir[6]
  PIN gpio1_dir[7]
    DIRECTION OUTPUT ;
    USE SIGNAL ;
    ANTENNADIFFAREA 0.708600 ;
    PORT
      LAYER Metal3 ;
        RECT 0.000 1518.940 0.400 1519.340 ;
    END
  END gpio1_dir[7]
  PIN gpio1_dir[8]
    DIRECTION OUTPUT ;
    USE SIGNAL ;
    ANTENNADIFFAREA 0.708600 ;
    PORT
      LAYER Metal3 ;
        RECT 0.000 1597.060 0.400 1597.460 ;
    END
  END gpio1_dir[8]
  PIN gpio1_dir[9]
    DIRECTION OUTPUT ;
    USE SIGNAL ;
    ANTENNADIFFAREA 0.708600 ;
    PORT
      LAYER Metal3 ;
        RECT 0.000 1624.780 0.400 1625.180 ;
    END
  END gpio1_dir[9]
  PIN gpio1_in[0]
    DIRECTION INPUT ;
    USE SIGNAL ;
    ANTENNAGATEAREA 0.109200 ;
    ANTENNADIFFAREA 2.015400 ;
    PORT
      LAYER Metal3 ;
        RECT 0.000 1564.300 0.400 1564.700 ;
    END
  END gpio1_in[0]
  PIN gpio1_in[10]
    DIRECTION INPUT ;
    USE SIGNAL ;
    ANTENNAGATEAREA 0.109200 ;
    ANTENNADIFFAREA 2.015400 ;
    PORT
      LAYER Metal3 ;
        RECT 0.000 1616.380 0.400 1616.780 ;
    END
  END gpio1_in[10]
  PIN gpio1_in[11]
    DIRECTION INPUT ;
    USE SIGNAL ;
    ANTENNAGATEAREA 0.109200 ;
    ANTENNADIFFAREA 2.015400 ;
    PORT
      LAYER Metal3 ;
        RECT 0.000 1518.100 0.400 1518.500 ;
    END
  END gpio1_in[11]
  PIN gpio1_in[12]
    DIRECTION INPUT ;
    USE SIGNAL ;
    ANTENNAGATEAREA 0.109200 ;
    PORT
      LAYER Metal3 ;
        RECT 0.000 1563.460 0.400 1563.860 ;
    END
  END gpio1_in[12]
  PIN gpio1_in[13]
    DIRECTION INPUT ;
    USE SIGNAL ;
    ANTENNAGATEAREA 0.109200 ;
    ANTENNADIFFAREA 4.030800 ;
    PORT
      LAYER Metal3 ;
        RECT 0.000 1595.380 0.400 1595.780 ;
    END
  END gpio1_in[13]
  PIN gpio1_in[14]
    DIRECTION INPUT ;
    USE SIGNAL ;
    ANTENNAGATEAREA 0.109200 ;
    ANTENNADIFFAREA 4.030800 ;
    PORT
      LAYER Metal3 ;
        RECT 0.000 1623.100 0.400 1623.500 ;
    END
  END gpio1_in[14]
  PIN gpio1_in[15]
    DIRECTION INPUT ;
    USE SIGNAL ;
    ANTENNAGATEAREA 0.109200 ;
    ANTENNADIFFAREA 2.015400 ;
    PORT
      LAYER Metal3 ;
        RECT 0.000 1517.260 0.400 1517.660 ;
    END
  END gpio1_in[15]
  PIN gpio1_in[16]
    DIRECTION INPUT ;
    USE SIGNAL ;
    ANTENNAGATEAREA 0.109200 ;
    ANTENNADIFFAREA 4.030800 ;
    PORT
      LAYER Metal3 ;
        RECT 0.000 1637.380 0.400 1637.780 ;
    END
  END gpio1_in[16]
  PIN gpio1_in[17]
    DIRECTION INPUT ;
    USE SIGNAL ;
    ANTENNAGATEAREA 0.109200 ;
    ANTENNADIFFAREA 2.015400 ;
    PORT
      LAYER Metal3 ;
        RECT 0.000 1653.340 0.400 1653.740 ;
    END
  END gpio1_in[17]
  PIN gpio1_in[18]
    DIRECTION INPUT ;
    USE SIGNAL ;
    ANTENNAGATEAREA 0.109200 ;
    ANTENNADIFFAREA 2.015400 ;
    PORT
      LAYER Metal3 ;
        RECT 0.000 1561.780 0.400 1562.180 ;
    END
  END gpio1_in[18]
  PIN gpio1_in[19]
    DIRECTION INPUT ;
    USE SIGNAL ;
    ANTENNAGATEAREA 0.109200 ;
    ANTENNADIFFAREA 4.030800 ;
    PORT
      LAYER Metal3 ;
        RECT 0.000 1593.700 0.400 1594.100 ;
    END
  END gpio1_in[19]
  PIN gpio1_in[1]
    DIRECTION INPUT ;
    USE SIGNAL ;
    ANTENNAGATEAREA 0.109200 ;
    PORT
      LAYER Metal3 ;
        RECT 0.000 1516.420 0.400 1516.820 ;
    END
  END gpio1_in[1]
  PIN gpio1_in[20]
    DIRECTION INPUT ;
    USE SIGNAL ;
    ANTENNAGATEAREA 0.109200 ;
    PORT
      LAYER Metal3 ;
        RECT 0.000 1502.980 0.400 1503.380 ;
    END
  END gpio1_in[20]
  PIN gpio1_in[21]
    DIRECTION INPUT ;
    USE SIGNAL ;
    ANTENNAGATEAREA 0.109200 ;
    ANTENNADIFFAREA 2.015400 ;
    PORT
      LAYER Metal3 ;
        RECT 0.000 1634.860 0.400 1635.260 ;
    END
  END gpio1_in[21]
  PIN gpio1_in[22]
    DIRECTION INPUT ;
    USE SIGNAL ;
    ANTENNAGATEAREA 0.109200 ;
    ANTENNADIFFAREA 4.030800 ;
    PORT
      LAYER Metal3 ;
        RECT 0.000 1613.860 0.400 1614.260 ;
    END
  END gpio1_in[22]
  PIN gpio1_in[23]
    DIRECTION INPUT ;
    USE SIGNAL ;
    ANTENNAGATEAREA 0.109200 ;
    PORT
      LAYER Metal3 ;
        RECT 0.000 1515.580 0.400 1515.980 ;
    END
  END gpio1_in[23]
  PIN gpio1_in[24]
    DIRECTION INPUT ;
    USE SIGNAL ;
    ANTENNAGATEAREA 0.109200 ;
    ANTENNADIFFAREA 4.030800 ;
    PORT
      LAYER Metal3 ;
        RECT 0.000 1592.020 0.400 1592.420 ;
    END
  END gpio1_in[24]
  PIN gpio1_in[25]
    DIRECTION INPUT ;
    USE SIGNAL ;
    ANTENNAGATEAREA 0.109200 ;
    ANTENNADIFFAREA 2.015400 ;
    PORT
      LAYER Metal3 ;
        RECT 0.000 1633.180 0.400 1633.580 ;
    END
  END gpio1_in[25]
  PIN gpio1_in[26]
    DIRECTION INPUT ;
    USE SIGNAL ;
    ANTENNAGATEAREA 0.109200 ;
    PORT
      LAYER Metal3 ;
        RECT 0.000 1559.260 0.400 1559.660 ;
    END
  END gpio1_in[26]
  PIN gpio1_in[27]
    DIRECTION INPUT ;
    USE SIGNAL ;
    ANTENNAGATEAREA 0.109200 ;
    ANTENNADIFFAREA 2.015400 ;
    PORT
      LAYER Metal3 ;
        RECT 0.000 1502.140 0.400 1502.540 ;
    END
  END gpio1_in[27]
  PIN gpio1_in[28]
    DIRECTION INPUT ;
    USE SIGNAL ;
    ANTENNAGATEAREA 0.109200 ;
    PORT
      LAYER Metal3 ;
        RECT 0.000 1511.380 0.400 1511.780 ;
    END
  END gpio1_in[28]
  PIN gpio1_in[29]
    DIRECTION INPUT ;
    USE SIGNAL ;
    ANTENNAGATEAREA 0.109200 ;
    ANTENNADIFFAREA 4.030800 ;
    PORT
      LAYER Metal3 ;
        RECT 0.000 1558.420 0.400 1558.820 ;
    END
  END gpio1_in[29]
  PIN gpio1_in[2]
    DIRECTION INPUT ;
    USE SIGNAL ;
    ANTENNAGATEAREA 0.109200 ;
    ANTENNADIFFAREA 2.015400 ;
    PORT
      LAYER Metal3 ;
        RECT 0.000 1514.740 0.400 1515.140 ;
    END
  END gpio1_in[2]
  PIN gpio1_in[30]
    DIRECTION INPUT ;
    USE SIGNAL ;
    ANTENNAGATEAREA 0.109200 ;
    ANTENNADIFFAREA 4.030800 ;
    PORT
      LAYER Metal3 ;
        RECT 0.000 1602.100 0.400 1602.500 ;
    END
  END gpio1_in[30]
  PIN gpio1_in[31]
    DIRECTION INPUT ;
    USE SIGNAL ;
    ANTENNAGATEAREA 0.109200 ;
    ANTENNADIFFAREA 4.030800 ;
    PORT
      LAYER Metal3 ;
        RECT 0.000 1557.580 0.400 1557.980 ;
    END
  END gpio1_in[31]
  PIN gpio1_in[3]
    DIRECTION INPUT ;
    USE SIGNAL ;
    ANTENNAGATEAREA 0.109200 ;
    PORT
      LAYER Metal3 ;
        RECT 0.000 1617.220 0.400 1617.620 ;
    END
  END gpio1_in[3]
  PIN gpio1_in[4]
    DIRECTION INPUT ;
    USE SIGNAL ;
    ANTENNAGATEAREA 0.109200 ;
    ANTENNADIFFAREA 2.015400 ;
    PORT
      LAYER Metal3 ;
        RECT 0.000 1513.900 0.400 1514.300 ;
    END
  END gpio1_in[4]
  PIN gpio1_in[5]
    DIRECTION INPUT ;
    USE SIGNAL ;
    ANTENNAGATEAREA 0.109200 ;
    ANTENNADIFFAREA 2.015400 ;
    PORT
      LAYER Metal3 ;
        RECT 0.000 1496.260 0.400 1496.660 ;
    END
  END gpio1_in[5]
  PIN gpio1_in[6]
    DIRECTION INPUT ;
    USE SIGNAL ;
    ANTENNAGATEAREA 0.109200 ;
    ANTENNADIFFAREA 2.015400 ;
    PORT
      LAYER Metal3 ;
        RECT 0.000 1588.660 0.400 1589.060 ;
    END
  END gpio1_in[6]
  PIN gpio1_in[7]
    DIRECTION INPUT ;
    USE SIGNAL ;
    ANTENNAGATEAREA 0.109200 ;
    PORT
      LAYER Metal3 ;
        RECT 0.000 1628.140 0.400 1628.540 ;
    END
  END gpio1_in[7]
  PIN gpio1_in[8]
    DIRECTION INPUT ;
    USE SIGNAL ;
    ANTENNAGATEAREA 0.109200 ;
    ANTENNADIFFAREA 2.015400 ;
    PORT
      LAYER Metal3 ;
        RECT 0.000 1513.060 0.400 1513.460 ;
    END
  END gpio1_in[8]
  PIN gpio1_in[9]
    DIRECTION INPUT ;
    USE SIGNAL ;
    ANTENNAGATEAREA 0.109200 ;
    PORT
      LAYER Metal3 ;
        RECT 0.000 1627.300 0.400 1627.700 ;
    END
  END gpio1_in[9]
  PIN gpio1_out[0]
    DIRECTION OUTPUT ;
    USE SIGNAL ;
    ANTENNADIFFAREA 0.708600 ;
    PORT
      LAYER Metal3 ;
        RECT 0.000 1620.580 0.400 1620.980 ;
    END
  END gpio1_out[0]
  PIN gpio1_out[10]
    DIRECTION OUTPUT ;
    USE SIGNAL ;
    ANTENNADIFFAREA 0.708600 ;
    PORT
      LAYER Metal3 ;
        RECT 0.000 1555.060 0.400 1555.460 ;
    END
  END gpio1_out[10]
  PIN gpio1_out[11]
    DIRECTION OUTPUT ;
    USE SIGNAL ;
    ANTENNADIFFAREA 0.708600 ;
    PORT
      LAYER Metal3 ;
        RECT 0.000 1510.540 0.400 1510.940 ;
    END
  END gpio1_out[11]
  PIN gpio1_out[12]
    DIRECTION OUTPUT ;
    USE SIGNAL ;
    ANTENNADIFFAREA 0.708600 ;
    PORT
      LAYER Metal3 ;
        RECT 0.000 1501.300 0.400 1501.700 ;
    END
  END gpio1_out[12]
  PIN gpio1_out[13]
    DIRECTION OUTPUT ;
    USE SIGNAL ;
    ANTENNADIFFAREA 0.708600 ;
    PORT
      LAYER Metal3 ;
        RECT 0.000 1554.220 0.400 1554.620 ;
    END
  END gpio1_out[13]
  PIN gpio1_out[14]
    DIRECTION OUTPUT ;
    USE SIGNAL ;
    ANTENNADIFFAREA 0.708600 ;
    PORT
      LAYER Metal3 ;
        RECT 0.000 1512.220 0.400 1512.620 ;
    END
  END gpio1_out[14]
  PIN gpio1_out[15]
    DIRECTION OUTPUT ;
    USE SIGNAL ;
    ANTENNADIFFAREA 0.708600 ;
    PORT
      LAYER Metal3 ;
        RECT 0.000 1650.820 0.400 1651.220 ;
    END
  END gpio1_out[15]
  PIN gpio1_out[16]
    DIRECTION OUTPUT ;
    USE SIGNAL ;
    ANTENNADIFFAREA 0.708600 ;
    PORT
      LAYER Metal3 ;
        RECT 0.000 1553.380 0.400 1553.780 ;
    END
  END gpio1_out[16]
  PIN gpio1_out[17]
    DIRECTION OUTPUT ;
    USE SIGNAL ;
    ANTENNADIFFAREA 0.708600 ;
    PORT
      LAYER Metal3 ;
        RECT 0.000 1585.300 0.400 1585.700 ;
    END
  END gpio1_out[17]
  PIN gpio1_out[18]
    DIRECTION OUTPUT ;
    USE SIGNAL ;
    ANTENNADIFFAREA 0.708600 ;
    PORT
      LAYER Metal3 ;
        RECT 0.000 1615.540 0.400 1615.940 ;
    END
  END gpio1_out[18]
  PIN gpio1_out[19]
    DIRECTION OUTPUT ;
    USE SIGNAL ;
    ANTENNADIFFAREA 0.708600 ;
    PORT
      LAYER Metal3 ;
        RECT 0.000 1493.740 0.400 1494.140 ;
    END
  END gpio1_out[19]
  PIN gpio1_out[1]
    DIRECTION OUTPUT ;
    USE SIGNAL ;
    ANTENNADIFFAREA 0.708600 ;
    PORT
      LAYER Metal3 ;
        RECT 0.000 1622.260 0.400 1622.660 ;
    END
  END gpio1_out[1]
  PIN gpio1_out[20]
    DIRECTION OUTPUT ;
    USE SIGNAL ;
    ANTENNADIFFAREA 0.708600 ;
    PORT
      LAYER Metal3 ;
        RECT 0.000 1596.220 0.400 1596.620 ;
    END
  END gpio1_out[20]
  PIN gpio1_out[21]
    DIRECTION OUTPUT ;
    USE SIGNAL ;
    ANTENNADIFFAREA 0.708600 ;
    PORT
      LAYER Metal3 ;
        RECT 0.000 1551.700 0.400 1552.100 ;
    END
  END gpio1_out[21]
  PIN gpio1_out[22]
    DIRECTION OUTPUT ;
    USE SIGNAL ;
    ANTENNADIFFAREA 0.708600 ;
    PORT
      LAYER Metal3 ;
        RECT 0.000 1583.620 0.400 1584.020 ;
    END
  END gpio1_out[22]
  PIN gpio1_out[23]
    DIRECTION OUTPUT ;
    USE SIGNAL ;
    ANTENNADIFFAREA 0.708600 ;
    PORT
      LAYER Metal3 ;
        RECT 0.000 1500.460 0.400 1500.860 ;
    END
  END gpio1_out[23]
  PIN gpio1_out[24]
    DIRECTION OUTPUT ;
    USE SIGNAL ;
    ANTENNADIFFAREA 0.708600 ;
    PORT
      LAYER Metal3 ;
        RECT 0.000 1550.860 0.400 1551.260 ;
    END
  END gpio1_out[24]
  PIN gpio1_out[25]
    DIRECTION OUTPUT ;
    USE SIGNAL ;
    ANTENNADIFFAREA 0.708600 ;
    PORT
      LAYER Metal3 ;
        RECT 0.000 1619.740 0.400 1620.140 ;
    END
  END gpio1_out[25]
  PIN gpio1_out[26]
    DIRECTION OUTPUT ;
    USE SIGNAL ;
    ANTENNADIFFAREA 0.708600 ;
    PORT
      LAYER Metal3 ;
        RECT 0.000 1570.180 0.400 1570.580 ;
    END
  END gpio1_out[26]
  PIN gpio1_out[27]
    DIRECTION OUTPUT ;
    USE SIGNAL ;
    ANTENNADIFFAREA 0.708600 ;
    PORT
      LAYER Metal3 ;
        RECT 0.000 1550.020 0.400 1550.420 ;
    END
  END gpio1_out[27]
  PIN gpio1_out[28]
    DIRECTION OUTPUT ;
    USE SIGNAL ;
    ANTENNADIFFAREA 0.708600 ;
    PORT
      LAYER Metal3 ;
        RECT 0.000 1581.940 0.400 1582.340 ;
    END
  END gpio1_out[28]
  PIN gpio1_out[29]
    DIRECTION OUTPUT ;
    USE SIGNAL ;
    ANTENNADIFFAREA 0.708600 ;
    PORT
      LAYER Metal3 ;
        RECT 0.000 1618.060 0.400 1618.460 ;
    END
  END gpio1_out[29]
  PIN gpio1_out[2]
    DIRECTION OUTPUT ;
    USE SIGNAL ;
    ANTENNADIFFAREA 0.708600 ;
    PORT
      LAYER Metal3 ;
        RECT 0.000 1549.180 0.400 1549.580 ;
    END
  END gpio1_out[2]
  PIN gpio1_out[30]
    DIRECTION OUTPUT ;
    USE SIGNAL ;
    ANTENNADIFFAREA 0.708600 ;
    PORT
      LAYER Metal3 ;
        RECT 0.000 1606.300 0.400 1606.700 ;
    END
  END gpio1_out[30]
  PIN gpio1_out[31]
    DIRECTION OUTPUT ;
    USE SIGNAL ;
    ANTENNADIFFAREA 0.708600 ;
    PORT
      LAYER Metal3 ;
        RECT 0.000 1539.100 0.400 1539.500 ;
    END
  END gpio1_out[31]
  PIN gpio1_out[3]
    DIRECTION OUTPUT ;
    USE SIGNAL ;
    ANTENNADIFFAREA 0.708600 ;
    PORT
      LAYER Metal3 ;
        RECT 0.000 1548.340 0.400 1548.740 ;
    END
  END gpio1_out[3]
  PIN gpio1_out[4]
    DIRECTION OUTPUT ;
    USE SIGNAL ;
    ANTENNADIFFAREA 0.708600 ;
    PORT
      LAYER Metal3 ;
        RECT 0.000 1580.260 0.400 1580.660 ;
    END
  END gpio1_out[4]
  PIN gpio1_out[5]
    DIRECTION OUTPUT ;
    USE SIGNAL ;
    ANTENNADIFFAREA 0.708600 ;
    PORT
      LAYER Metal3 ;
        RECT 0.000 1612.180 0.400 1612.580 ;
    END
  END gpio1_out[5]
  PIN gpio1_out[6]
    DIRECTION OUTPUT ;
    USE SIGNAL ;
    ANTENNADIFFAREA 0.708600 ;
    PORT
      LAYER Metal3 ;
        RECT 0.000 1547.500 0.400 1547.900 ;
    END
  END gpio1_out[6]
  PIN gpio1_out[7]
    DIRECTION OUTPUT ;
    USE SIGNAL ;
    ANTENNADIFFAREA 0.708600 ;
    PORT
      LAYER Metal3 ;
        RECT 0.000 1599.580 0.400 1599.980 ;
    END
  END gpio1_out[7]
  PIN gpio1_out[8]
    DIRECTION OUTPUT ;
    USE SIGNAL ;
    ANTENNADIFFAREA 0.708600 ;
    PORT
      LAYER Metal3 ;
        RECT 0.000 1644.100 0.400 1644.500 ;
    END
  END gpio1_out[8]
  PIN gpio1_out[9]
    DIRECTION OUTPUT ;
    USE SIGNAL ;
    ANTENNADIFFAREA 0.708600 ;
    PORT
      LAYER Metal3 ;
        RECT 0.000 1495.420 0.400 1495.820 ;
    END
  END gpio1_out[9]
  PIN gpio2_dir[0]
    DIRECTION OUTPUT ;
    USE SIGNAL ;
    ANTENNADIFFAREA 0.708600 ;
    PORT
      LAYER Metal3 ;
        RECT 0.000 1578.580 0.400 1578.980 ;
    END
  END gpio2_dir[0]
  PIN gpio2_dir[10]
    DIRECTION OUTPUT ;
    USE SIGNAL ;
    ANTENNADIFFAREA 0.708600 ;
    PORT
      LAYER Metal3 ;
        RECT 0.000 1613.020 0.400 1613.420 ;
    END
  END gpio2_dir[10]
  PIN gpio2_dir[11]
    DIRECTION OUTPUT ;
    USE SIGNAL ;
    ANTENNADIFFAREA 0.708600 ;
    PORT
      LAYER Metal3 ;
        RECT 0.000 1545.820 0.400 1546.220 ;
    END
  END gpio2_dir[11]
  PIN gpio2_dir[12]
    DIRECTION OUTPUT ;
    USE SIGNAL ;
    ANTENNADIFFAREA 0.708600 ;
    PORT
      LAYER Metal3 ;
        RECT 0.000 1541.620 0.400 1542.020 ;
    END
  END gpio2_dir[12]
  PIN gpio2_dir[13]
    DIRECTION OUTPUT ;
    USE SIGNAL ;
    ANTENNADIFFAREA 0.708600 ;
    PORT
      LAYER Metal3 ;
        RECT 0.000 1499.620 0.400 1500.020 ;
    END
  END gpio2_dir[13]
  PIN gpio2_dir[14]
    DIRECTION OUTPUT ;
    USE SIGNAL ;
    ANTENNADIFFAREA 0.708600 ;
    PORT
      LAYER Metal3 ;
        RECT 0.000 1544.980 0.400 1545.380 ;
    END
  END gpio2_dir[14]
  PIN gpio2_dir[15]
    DIRECTION OUTPUT ;
    USE SIGNAL ;
    ANTENNADIFFAREA 0.708600 ;
    PORT
      LAYER Metal3 ;
        RECT 0.000 1576.900 0.400 1577.300 ;
    END
  END gpio2_dir[15]
  PIN gpio2_dir[16]
    DIRECTION OUTPUT ;
    USE SIGNAL ;
    ANTENNADIFFAREA 0.708600 ;
    PORT
      LAYER Metal3 ;
        RECT 0.000 1610.500 0.400 1610.900 ;
    END
  END gpio2_dir[16]
  PIN gpio2_dir[17]
    DIRECTION OUTPUT ;
    USE SIGNAL ;
    ANTENNADIFFAREA 0.708600 ;
    PORT
      LAYER Metal3 ;
        RECT 0.000 1544.140 0.400 1544.540 ;
    END
  END gpio2_dir[17]
  PIN gpio2_dir[18]
    DIRECTION OUTPUT ;
    USE SIGNAL ;
    ANTENNADIFFAREA 0.708600 ;
    PORT
      LAYER Metal3 ;
        RECT 0.000 1609.660 0.400 1610.060 ;
    END
  END gpio2_dir[18]
  PIN gpio2_dir[19]
    DIRECTION OUTPUT ;
    USE SIGNAL ;
    ANTENNADIFFAREA 0.708600 ;
    PORT
      LAYER Metal3 ;
        RECT 0.000 1498.780 0.400 1499.180 ;
    END
  END gpio2_dir[19]
  PIN gpio2_dir[1]
    DIRECTION OUTPUT ;
    USE SIGNAL ;
    ANTENNADIFFAREA 0.708600 ;
    PORT
      LAYER Metal3 ;
        RECT 0.000 1543.300 0.400 1543.700 ;
    END
  END gpio2_dir[1]
  PIN gpio2_dir[20]
    DIRECTION OUTPUT ;
    USE SIGNAL ;
    ANTENNADIFFAREA 0.708600 ;
    PORT
      LAYER Metal3 ;
        RECT 0.000 1575.220 0.400 1575.620 ;
    END
  END gpio2_dir[20]
  PIN gpio2_dir[21]
    DIRECTION OUTPUT ;
    USE SIGNAL ;
    ANTENNADIFFAREA 0.708600 ;
    PORT
      LAYER Metal3 ;
        RECT 0.000 1607.980 0.400 1608.380 ;
    END
  END gpio2_dir[21]
  PIN gpio2_dir[22]
    DIRECTION OUTPUT ;
    USE SIGNAL ;
    ANTENNADIFFAREA 0.708600 ;
    PORT
      LAYER Metal3 ;
        RECT 0.000 1542.460 0.400 1542.860 ;
    END
  END gpio2_dir[22]
  PIN gpio2_dir[23]
    DIRECTION OUTPUT ;
    USE SIGNAL ;
    ANTENNADIFFAREA 0.708600 ;
    PORT
      LAYER Metal3 ;
        RECT 0.000 1607.140 0.400 1607.540 ;
    END
  END gpio2_dir[23]
  PIN gpio2_dir[24]
    DIRECTION OUTPUT ;
    USE SIGNAL ;
    ANTENNADIFFAREA 0.708600 ;
    PORT
      LAYER Metal3 ;
        RECT 0.000 1646.620 0.400 1647.020 ;
    END
  END gpio2_dir[24]
  PIN gpio2_dir[25]
    DIRECTION OUTPUT ;
    USE SIGNAL ;
    ANTENNADIFFAREA 0.708600 ;
    PORT
      LAYER Metal3 ;
        RECT 0.000 1531.540 0.400 1531.940 ;
    END
  END gpio2_dir[25]
  PIN gpio2_dir[26]
    DIRECTION OUTPUT ;
    USE SIGNAL ;
    ANTENNADIFFAREA 0.708600 ;
    PORT
      LAYER Metal3 ;
        RECT 0.000 1573.540 0.400 1573.940 ;
    END
  END gpio2_dir[26]
  PIN gpio2_dir[27]
    DIRECTION OUTPUT ;
    USE SIGNAL ;
    ANTENNADIFFAREA 0.708600 ;
    PORT
      LAYER Metal3 ;
        RECT 0.000 1605.460 0.400 1605.860 ;
    END
  END gpio2_dir[27]
  PIN gpio2_dir[28]
    DIRECTION OUTPUT ;
    USE SIGNAL ;
    ANTENNADIFFAREA 0.708600 ;
    PORT
      LAYER Metal3 ;
        RECT 0.000 1540.780 0.400 1541.180 ;
    END
  END gpio2_dir[28]
  PIN gpio2_dir[29]
    DIRECTION OUTPUT ;
    USE SIGNAL ;
    ANTENNADIFFAREA 0.708600 ;
    PORT
      LAYER Metal3 ;
        RECT 0.000 1604.620 0.400 1605.020 ;
    END
  END gpio2_dir[29]
  PIN gpio2_dir[2]
    DIRECTION OUTPUT ;
    USE SIGNAL ;
    ANTENNADIFFAREA 0.708600 ;
    PORT
      LAYER Metal3 ;
        RECT 0.000 1586.980 0.400 1587.380 ;
    END
  END gpio2_dir[2]
  PIN gpio2_dir[30]
    DIRECTION OUTPUT ;
    USE SIGNAL ;
    ANTENNADIFFAREA 0.708600 ;
    PORT
      LAYER Metal3 ;
        RECT 0.000 1539.940 0.400 1540.340 ;
    END
  END gpio2_dir[30]
  PIN gpio2_dir[31]
    DIRECTION OUTPUT ;
    USE SIGNAL ;
    ANTENNADIFFAREA 0.708600 ;
    PORT
      LAYER Metal3 ;
        RECT 0.000 1590.340 0.400 1590.740 ;
    END
  END gpio2_dir[31]
  PIN gpio2_dir[3]
    DIRECTION OUTPUT ;
    USE SIGNAL ;
    ANTENNADIFFAREA 0.708600 ;
    PORT
      LAYER Metal3 ;
        RECT 0.000 1602.940 0.400 1603.340 ;
    END
  END gpio2_dir[3]
  PIN gpio2_dir[4]
    DIRECTION OUTPUT ;
    USE SIGNAL ;
    ANTENNADIFFAREA 0.708600 ;
    PORT
      LAYER Metal3 ;
        RECT 0.000 1635.700 0.400 1636.100 ;
    END
  END gpio2_dir[4]
  PIN gpio2_dir[5]
    DIRECTION OUTPUT ;
    USE SIGNAL ;
    ANTENNADIFFAREA 0.708600 ;
    PORT
      LAYER Metal3 ;
        RECT 0.000 1509.700 0.400 1510.100 ;
    END
  END gpio2_dir[5]
  PIN gpio2_dir[6]
    DIRECTION OUTPUT ;
    USE SIGNAL ;
    ANTENNADIFFAREA 0.708600 ;
    PORT
      LAYER Metal3 ;
        RECT 0.000 1571.020 0.400 1571.420 ;
    END
  END gpio2_dir[6]
  PIN gpio2_dir[7]
    DIRECTION OUTPUT ;
    USE SIGNAL ;
    ANTENNADIFFAREA 0.708600 ;
    PORT
      LAYER Metal3 ;
        RECT 0.000 1601.260 0.400 1601.660 ;
    END
  END gpio2_dir[7]
  PIN gpio2_dir[8]
    DIRECTION OUTPUT ;
    USE SIGNAL ;
    ANTENNADIFFAREA 0.708600 ;
    PORT
      LAYER Metal3 ;
        RECT 0.000 1632.340 0.400 1632.740 ;
    END
  END gpio2_dir[8]
  PIN gpio2_dir[9]
    DIRECTION OUTPUT ;
    USE SIGNAL ;
    ANTENNADIFFAREA 0.708600 ;
    PORT
      LAYER Metal3 ;
        RECT 0.000 1538.260 0.400 1538.660 ;
    END
  END gpio2_dir[9]
  PIN gpio2_in[0]
    DIRECTION INPUT ;
    USE SIGNAL ;
    ANTENNAGATEAREA 0.109200 ;
    ANTENNADIFFAREA 2.015400 ;
    PORT
      LAYER Metal3 ;
        RECT 0.000 1621.420 0.400 1621.820 ;
    END
  END gpio2_in[0]
  PIN gpio2_in[10]
    DIRECTION INPUT ;
    USE SIGNAL ;
    ANTENNAGATEAREA 0.109200 ;
    ANTENNADIFFAREA 2.015400 ;
    PORT
      LAYER Metal3 ;
        RECT 0.000 1582.780 0.400 1583.180 ;
    END
  END gpio2_in[10]
  PIN gpio2_in[11]
    DIRECTION INPUT ;
    USE SIGNAL ;
    ANTENNAGATEAREA 0.109200 ;
    ANTENNADIFFAREA 2.015400 ;
    PORT
      LAYER Metal3 ;
        RECT 0.000 1649.140 0.400 1649.540 ;
    END
  END gpio2_in[11]
  PIN gpio2_in[12]
    DIRECTION INPUT ;
    USE SIGNAL ;
    ANTENNAGATEAREA 0.109200 ;
    ANTENNADIFFAREA 2.015400 ;
    PORT
      LAYER Metal3 ;
        RECT 0.000 1537.420 0.400 1537.820 ;
    END
  END gpio2_in[12]
  PIN gpio2_in[13]
    DIRECTION INPUT ;
    USE SIGNAL ;
    ANTENNAGATEAREA 0.109200 ;
    ANTENNADIFFAREA 2.015400 ;
    PORT
      LAYER Metal3 ;
        RECT 0.000 1636.540 0.400 1636.940 ;
    END
  END gpio2_in[13]
  PIN gpio2_in[14]
    DIRECTION INPUT ;
    USE SIGNAL ;
    ANTENNAGATEAREA 0.109200 ;
    ANTENNADIFFAREA 2.015400 ;
    PORT
      LAYER Metal3 ;
        RECT 0.000 1597.900 0.400 1598.300 ;
    END
  END gpio2_in[14]
  PIN gpio2_in[15]
    DIRECTION INPUT ;
    USE SIGNAL ;
    ANTENNAGATEAREA 0.109200 ;
    ANTENNADIFFAREA 6.046200 ;
    PORT
      LAYER Metal3 ;
        RECT 0.000 1648.300 0.400 1648.700 ;
    END
  END gpio2_in[15]
  PIN gpio2_in[16]
    DIRECTION INPUT ;
    USE SIGNAL ;
    ANTENNAGATEAREA 0.109200 ;
    ANTENNADIFFAREA 2.015400 ;
    PORT
      LAYER Metal3 ;
        RECT 0.000 1536.580 0.400 1536.980 ;
    END
  END gpio2_in[16]
  PIN gpio2_in[17]
    DIRECTION INPUT ;
    USE SIGNAL ;
    ANTENNAGATEAREA 0.109200 ;
    ANTENNADIFFAREA 2.015400 ;
    PORT
      LAYER Metal3 ;
        RECT 0.000 1529.860 0.400 1530.260 ;
    END
  END gpio2_in[17]
  PIN gpio2_in[18]
    DIRECTION INPUT ;
    USE SIGNAL ;
    ANTENNAGATEAREA 0.109200 ;
    ANTENNADIFFAREA 2.015400 ;
    PORT
      LAYER Metal3 ;
        RECT 0.000 1567.660 0.400 1568.060 ;
    END
  END gpio2_in[18]
  PIN gpio2_in[19]
    DIRECTION INPUT ;
    USE SIGNAL ;
    ANTENNAGATEAREA 0.109200 ;
    ANTENNADIFFAREA 2.015400 ;
    PORT
      LAYER Metal3 ;
        RECT 0.000 1618.900 0.400 1619.300 ;
    END
  END gpio2_in[19]
  PIN gpio2_in[1]
    DIRECTION INPUT ;
    USE SIGNAL ;
    ANTENNAGATEAREA 0.109200 ;
    ANTENNADIFFAREA 2.015400 ;
    PORT
      LAYER Metal3 ;
        RECT 0.000 1535.740 0.400 1536.140 ;
    END
  END gpio2_in[1]
  PIN gpio2_in[20]
    DIRECTION INPUT ;
    USE SIGNAL ;
    ANTENNAGATEAREA 0.109200 ;
    ANTENNADIFFAREA 2.015400 ;
    PORT
      LAYER Metal3 ;
        RECT 0.000 1508.860 0.400 1509.260 ;
    END
  END gpio2_in[20]
  PIN gpio2_in[21]
    DIRECTION INPUT ;
    USE SIGNAL ;
    ANTENNAGATEAREA 0.109200 ;
    ANTENNADIFFAREA 2.015400 ;
    PORT
      LAYER Metal3 ;
        RECT 0.000 1527.340 0.400 1527.740 ;
    END
  END gpio2_in[21]
  PIN gpio2_in[22]
    DIRECTION INPUT ;
    USE SIGNAL ;
    ANTENNAGATEAREA 0.109200 ;
    ANTENNADIFFAREA 6.046200 ;
    PORT
      LAYER Metal3 ;
        RECT 0.000 1638.220 0.400 1638.620 ;
    END
  END gpio2_in[22]
  PIN gpio2_in[23]
    DIRECTION INPUT ;
    USE SIGNAL ;
    ANTENNAGATEAREA 0.109200 ;
    ANTENNADIFFAREA 2.015400 ;
    PORT
      LAYER Metal3 ;
        RECT 0.000 1534.900 0.400 1535.300 ;
    END
  END gpio2_in[23]
  PIN gpio2_in[24]
    DIRECTION INPUT ;
    USE SIGNAL ;
    ANTENNAGATEAREA 0.109200 ;
    ANTENNADIFFAREA 2.015400 ;
    PORT
      LAYER Metal3 ;
        RECT 0.000 1560.940 0.400 1561.340 ;
    END
  END gpio2_in[24]
  PIN gpio2_in[25]
    DIRECTION INPUT ;
    USE SIGNAL ;
    ANTENNAGATEAREA 0.109200 ;
    ANTENNADIFFAREA 2.015400 ;
    PORT
      LAYER Metal3 ;
        RECT 0.000 1592.860 0.400 1593.260 ;
    END
  END gpio2_in[25]
  PIN gpio2_in[26]
    DIRECTION INPUT ;
    USE SIGNAL ;
    ANTENNAGATEAREA 0.109200 ;
    ANTENNADIFFAREA 6.046200 ;
    PORT
      LAYER Metal3 ;
        RECT 0.000 1641.580 0.400 1641.980 ;
    END
  END gpio2_in[26]
  PIN gpio2_in[27]
    DIRECTION INPUT ;
    USE SIGNAL ;
    ANTENNAGATEAREA 0.109200 ;
    ANTENNADIFFAREA 6.046200 ;
    PORT
      LAYER Metal3 ;
        RECT 0.000 1534.060 0.400 1534.460 ;
    END
  END gpio2_in[27]
  PIN gpio2_in[28]
    DIRECTION INPUT ;
    USE SIGNAL ;
    ANTENNAGATEAREA 0.109200 ;
    ANTENNADIFFAREA 2.015400 ;
    PORT
      LAYER Metal3 ;
        RECT 0.000 1565.140 0.400 1565.540 ;
    END
  END gpio2_in[28]
  PIN gpio2_in[29]
    DIRECTION INPUT ;
    USE SIGNAL ;
    ANTENNAGATEAREA 0.109200 ;
    ANTENNADIFFAREA 2.015400 ;
    PORT
      LAYER Metal3 ;
        RECT 0.000 1591.180 0.400 1591.580 ;
    END
  END gpio2_in[29]
  PIN gpio2_in[2]
    DIRECTION INPUT ;
    USE SIGNAL ;
    ANTENNAGATEAREA 0.109200 ;
    ANTENNADIFFAREA 4.030800 ;
    PORT
      LAYER Metal3 ;
        RECT 0.000 1645.780 0.400 1646.180 ;
    END
  END gpio2_in[2]
  PIN gpio2_in[30]
    DIRECTION INPUT ;
    USE SIGNAL ;
    ANTENNAGATEAREA 0.109200 ;
    ANTENNADIFFAREA 2.015400 ;
    PORT
      LAYER Metal3 ;
        RECT 0.000 1533.220 0.400 1533.620 ;
    END
  END gpio2_in[30]
  PIN gpio2_in[31]
    DIRECTION INPUT ;
    USE SIGNAL ;
    ANTENNAGATEAREA 0.109200 ;
    ANTENNADIFFAREA 2.015400 ;
    PORT
      LAYER Metal3 ;
        RECT 0.000 1508.020 0.400 1508.420 ;
    END
  END gpio2_in[31]
  PIN gpio2_in[3]
    DIRECTION INPUT ;
    USE SIGNAL ;
    ANTENNAGATEAREA 0.109200 ;
    ANTENNADIFFAREA 2.015400 ;
    PORT
      LAYER Metal3 ;
        RECT 0.000 1589.500 0.400 1589.900 ;
    END
  END gpio2_in[3]
  PIN gpio2_in[4]
    DIRECTION INPUT ;
    USE SIGNAL ;
    ANTENNAGATEAREA 0.109200 ;
    ANTENNADIFFAREA 2.015400 ;
    PORT
      LAYER Metal3 ;
        RECT 0.000 1556.740 0.400 1557.140 ;
    END
  END gpio2_in[4]
  PIN gpio2_in[5]
    DIRECTION INPUT ;
    USE SIGNAL ;
    ANTENNAGATEAREA 0.109200 ;
    ANTENNADIFFAREA 2.015400 ;
    PORT
      LAYER Metal3 ;
        RECT 0.000 1532.380 0.400 1532.780 ;
    END
  END gpio2_in[5]
  PIN gpio2_in[6]
    DIRECTION INPUT ;
    USE SIGNAL ;
    ANTENNAGATEAREA 0.109200 ;
    ANTENNADIFFAREA 2.015400 ;
    PORT
      LAYER Metal3 ;
        RECT 0.000 1644.940 0.400 1645.340 ;
    END
  END gpio2_in[6]
  PIN gpio2_in[7]
    DIRECTION INPUT ;
    USE SIGNAL ;
    ANTENNAGATEAREA 0.109200 ;
    ANTENNADIFFAREA 2.015400 ;
    PORT
      LAYER Metal3 ;
        RECT 0.000 1587.820 0.400 1588.220 ;
    END
  END gpio2_in[7]
  PIN gpio2_in[8]
    DIRECTION INPUT ;
    USE SIGNAL ;
    ANTENNAGATEAREA 0.109200 ;
    ANTENNADIFFAREA 2.015400 ;
    PORT
      LAYER Metal3 ;
        RECT 0.000 1562.620 0.400 1563.020 ;
    END
  END gpio2_in[8]
  PIN gpio2_in[9]
    DIRECTION INPUT ;
    USE SIGNAL ;
    ANTENNAGATEAREA 0.109200 ;
    ANTENNADIFFAREA 4.030800 ;
    PORT
      LAYER Metal3 ;
        RECT 0.000 1494.580 0.400 1494.980 ;
    END
  END gpio2_in[9]
  PIN gpio2_out[0]
    DIRECTION OUTPUT ;
    USE SIGNAL ;
    ANTENNADIFFAREA 0.708600 ;
    PORT
      LAYER Metal3 ;
        RECT 0.000 1507.180 0.400 1507.580 ;
    END
  END gpio2_out[0]
  PIN gpio2_out[10]
    DIRECTION OUTPUT ;
    USE SIGNAL ;
    ANTENNADIFFAREA 0.708600 ;
    PORT
      LAYER Metal3 ;
        RECT 0.000 1586.140 0.400 1586.540 ;
    END
  END gpio2_out[10]
  PIN gpio2_out[11]
    DIRECTION OUTPUT ;
    USE SIGNAL ;
    ANTENNADIFFAREA 0.708600 ;
    PORT
      LAYER Metal3 ;
        RECT 0.000 1569.340 0.400 1569.740 ;
    END
  END gpio2_out[11]
  PIN gpio2_out[12]
    DIRECTION OUTPUT ;
    USE SIGNAL ;
    ANTENNADIFFAREA 0.708600 ;
    PORT
      LAYER Metal3 ;
        RECT 0.000 1530.700 0.400 1531.100 ;
    END
  END gpio2_out[12]
  PIN gpio2_out[13]
    DIRECTION OUTPUT ;
    USE SIGNAL ;
    ANTENNADIFFAREA 0.708600 ;
    PORT
      LAYER Metal3 ;
        RECT 0.000 1529.020 0.400 1529.420 ;
    END
  END gpio2_out[13]
  PIN gpio2_out[14]
    DIRECTION OUTPUT ;
    USE SIGNAL ;
    ANTENNADIFFAREA 0.708600 ;
    PORT
      LAYER Metal3 ;
        RECT 0.000 1584.460 0.400 1584.860 ;
    END
  END gpio2_out[14]
  PIN gpio2_out[15]
    DIRECTION OUTPUT ;
    USE SIGNAL ;
    ANTENNADIFFAREA 0.708600 ;
    PORT
      LAYER Metal3 ;
        RECT 0.000 1628.980 0.400 1629.380 ;
    END
  END gpio2_out[15]
  PIN gpio2_out[16]
    DIRECTION OUTPUT ;
    USE SIGNAL ;
    ANTENNADIFFAREA 0.708600 ;
    PORT
      LAYER Metal3 ;
        RECT 0.000 1506.340 0.400 1506.740 ;
    END
  END gpio2_out[16]
  PIN gpio2_out[17]
    DIRECTION OUTPUT ;
    USE SIGNAL ;
    ANTENNADIFFAREA 0.708600 ;
    PORT
      LAYER Metal3 ;
        RECT 0.000 1611.340 0.400 1611.740 ;
    END
  END gpio2_out[17]
  PIN gpio2_out[18]
    DIRECTION OUTPUT ;
    USE SIGNAL ;
    ANTENNADIFFAREA 0.708600 ;
    PORT
      LAYER Metal3 ;
        RECT 0.000 1560.100 0.400 1560.500 ;
    END
  END gpio2_out[18]
  PIN gpio2_out[19]
    DIRECTION OUTPUT ;
    USE SIGNAL ;
    ANTENNADIFFAREA 0.708600 ;
    PORT
      LAYER Metal3 ;
        RECT 0.000 1630.660 0.400 1631.060 ;
    END
  END gpio2_out[19]
  PIN gpio2_out[1]
    DIRECTION OUTPUT ;
    USE SIGNAL ;
    ANTENNADIFFAREA 0.708600 ;
    PORT
      LAYER Metal3 ;
        RECT 0.000 1523.980 0.400 1524.380 ;
    END
  END gpio2_out[1]
  PIN gpio2_out[20]
    DIRECTION OUTPUT ;
    USE SIGNAL ;
    ANTENNADIFFAREA 0.708600 ;
    PORT
      LAYER Metal3 ;
        RECT 0.000 1625.620 0.400 1626.020 ;
    END
  END gpio2_out[20]
  PIN gpio2_out[21]
    DIRECTION OUTPUT ;
    USE SIGNAL ;
    ANTENNADIFFAREA 0.708600 ;
    PORT
      LAYER Metal3 ;
        RECT 0.000 1581.100 0.400 1581.500 ;
    END
  END gpio2_out[21]
  PIN gpio2_out[22]
    DIRECTION OUTPUT ;
    USE SIGNAL ;
    ANTENNADIFFAREA 0.708600 ;
    PORT
      LAYER Metal3 ;
        RECT 0.000 1626.460 0.400 1626.860 ;
    END
  END gpio2_out[22]
  PIN gpio2_out[23]
    DIRECTION OUTPUT ;
    USE SIGNAL ;
    ANTENNADIFFAREA 0.708600 ;
    PORT
      LAYER Metal3 ;
        RECT 0.000 1528.180 0.400 1528.580 ;
    END
  END gpio2_out[23]
  PIN gpio2_out[24]
    DIRECTION OUTPUT ;
    USE SIGNAL ;
    ANTENNADIFFAREA 0.708600 ;
    PORT
      LAYER Metal3 ;
        RECT 0.000 1643.260 0.400 1643.660 ;
    END
  END gpio2_out[24]
  PIN gpio2_out[25]
    DIRECTION OUTPUT ;
    USE SIGNAL ;
    ANTENNADIFFAREA 0.708600 ;
    PORT
      LAYER Metal3 ;
        RECT 0.000 1579.420 0.400 1579.820 ;
    END
  END gpio2_out[25]
  PIN gpio2_out[26]
    DIRECTION OUTPUT ;
    USE SIGNAL ;
    ANTENNADIFFAREA 0.708600 ;
    PORT
      LAYER Metal3 ;
        RECT 0.000 1608.820 0.400 1609.220 ;
    END
  END gpio2_out[26]
  PIN gpio2_out[27]
    DIRECTION OUTPUT ;
    USE SIGNAL ;
    ANTENNADIFFAREA 0.708600 ;
    PORT
      LAYER Metal3 ;
        RECT 0.000 1497.940 0.400 1498.340 ;
    END
  END gpio2_out[27]
  PIN gpio2_out[28]
    DIRECTION OUTPUT ;
    USE SIGNAL ;
    ANTENNADIFFAREA 0.708600 ;
    PORT
      LAYER Metal3 ;
        RECT 0.000 1651.660 0.400 1652.060 ;
    END
  END gpio2_out[28]
  PIN gpio2_out[29]
    DIRECTION OUTPUT ;
    USE SIGNAL ;
    ANTENNADIFFAREA 0.708600 ;
    PORT
      LAYER Metal3 ;
        RECT 0.000 1577.740 0.400 1578.140 ;
    END
  END gpio2_out[29]
  PIN gpio2_out[2]
    DIRECTION OUTPUT ;
    USE SIGNAL ;
    ANTENNADIFFAREA 0.708600 ;
    PORT
      LAYER Metal3 ;
        RECT 0.000 1505.500 0.400 1505.900 ;
    END
  END gpio2_out[2]
  PIN gpio2_out[30]
    DIRECTION OUTPUT ;
    USE SIGNAL ;
    ANTENNADIFFAREA 0.708600 ;
    PORT
      LAYER Metal3 ;
        RECT 0.000 1526.500 0.400 1526.900 ;
    END
  END gpio2_out[30]
  PIN gpio2_out[31]
    DIRECTION OUTPUT ;
    USE SIGNAL ;
    ANTENNADIFFAREA 0.708600 ;
    PORT
      LAYER Metal3 ;
        RECT 0.000 1652.500 0.400 1652.900 ;
    END
  END gpio2_out[31]
  PIN gpio2_out[3]
    DIRECTION OUTPUT ;
    USE SIGNAL ;
    ANTENNADIFFAREA 0.708600 ;
    PORT
      LAYER Metal3 ;
        RECT 0.000 1576.060 0.400 1576.460 ;
    END
  END gpio2_out[3]
  PIN gpio2_out[4]
    DIRECTION OUTPUT ;
    USE SIGNAL ;
    ANTENNADIFFAREA 0.708600 ;
    PORT
      LAYER Metal3 ;
        RECT 0.000 1614.700 0.400 1615.100 ;
    END
  END gpio2_out[4]
  PIN gpio2_out[5]
    DIRECTION OUTPUT ;
    USE SIGNAL ;
    ANTENNADIFFAREA 0.708600 ;
    PORT
      LAYER Metal3 ;
        RECT 0.000 1525.660 0.400 1526.060 ;
    END
  END gpio2_out[5]
  PIN gpio2_out[6]
    DIRECTION OUTPUT ;
    USE SIGNAL ;
    ANTENNADIFFAREA 0.708600 ;
    PORT
      LAYER Metal3 ;
        RECT 0.000 1555.900 0.400 1556.300 ;
    END
  END gpio2_out[6]
  PIN gpio2_out[7]
    DIRECTION OUTPUT ;
    USE SIGNAL ;
    ANTENNADIFFAREA 0.708600 ;
    PORT
      LAYER Metal3 ;
        RECT 0.000 1574.380 0.400 1574.780 ;
    END
  END gpio2_out[7]
  PIN gpio2_out[8]
    DIRECTION OUTPUT ;
    USE SIGNAL ;
    ANTENNADIFFAREA 0.708600 ;
    PORT
      LAYER Metal3 ;
        RECT 0.000 1594.540 0.400 1594.940 ;
    END
  END gpio2_out[8]
  PIN gpio2_out[9]
    DIRECTION OUTPUT ;
    USE SIGNAL ;
    ANTENNADIFFAREA 0.708600 ;
    PORT
      LAYER Metal3 ;
        RECT 0.000 1524.820 0.400 1525.220 ;
    END
  END gpio2_out[9]
  PIN rst_ni
    DIRECTION INPUT ;
    USE SIGNAL ;
    ANTENNAGATEAREA 0.903500 ;
    ANTENNADIFFAREA 72.554398 ;
    PORT
      LAYER Metal3 ;
        RECT 0.000 1492.060 0.400 1492.460 ;
    END
  END rst_ni
  PIN spi_cs_n
    DIRECTION OUTPUT ;
    USE SIGNAL ;
    ANTENNADIFFAREA 0.708600 ;
    PORT
      LAYER Metal3 ;
        RECT 0.000 1222.420 0.400 1222.820 ;
    END
  END spi_cs_n
  PIN spi_miso
    DIRECTION INPUT ;
    USE SIGNAL ;
    ANTENNAGATEAREA 0.109200 ;
    ANTENNADIFFAREA 2.015400 ;
    PORT
      LAYER Metal3 ;
        RECT 0.000 1058.620 0.400 1059.020 ;
    END
  END spi_miso
  PIN spi_mosi
    DIRECTION OUTPUT ;
    USE SIGNAL ;
    ANTENNADIFFAREA 0.708600 ;
    PORT
      LAYER Metal3 ;
        RECT 0.000 950.260 0.400 950.660 ;
    END
  END spi_mosi
  PIN spi_sclk
    DIRECTION OUTPUT ;
    USE SIGNAL ;
    ANTENNADIFFAREA 0.708600 ;
    PORT
      LAYER Metal3 ;
        RECT 0.000 1014.940 0.400 1015.340 ;
    END
  END spi_sclk
  OBS
      LAYER GatPoly ;
        RECT 84.000 83.010 1559.040 1670.910 ;
      LAYER Metal1 ;
        RECT 84.000 82.940 1559.040 1670.980 ;
      LAYER Metal2 ;
        RECT 0.375 68.735 1576.905 1710.805 ;
      LAYER Metal3 ;
        RECT 0.100 1653.950 1587.025 1710.760 ;
        RECT 0.610 1653.130 1587.025 1653.950 ;
        RECT 0.100 1653.110 1587.025 1653.130 ;
        RECT 0.610 1652.290 1587.025 1653.110 ;
        RECT 0.100 1652.270 1587.025 1652.290 ;
        RECT 0.610 1651.450 1587.025 1652.270 ;
        RECT 0.100 1651.430 1587.025 1651.450 ;
        RECT 0.610 1650.610 1587.025 1651.430 ;
        RECT 0.100 1650.590 1587.025 1650.610 ;
        RECT 0.610 1649.770 1587.025 1650.590 ;
        RECT 0.100 1649.750 1587.025 1649.770 ;
        RECT 0.610 1648.930 1587.025 1649.750 ;
        RECT 0.100 1648.910 1587.025 1648.930 ;
        RECT 0.610 1648.090 1587.025 1648.910 ;
        RECT 0.100 1648.070 1587.025 1648.090 ;
        RECT 0.610 1647.250 1587.025 1648.070 ;
        RECT 0.100 1647.230 1587.025 1647.250 ;
        RECT 0.610 1646.410 1587.025 1647.230 ;
        RECT 0.100 1646.390 1587.025 1646.410 ;
        RECT 0.610 1645.570 1587.025 1646.390 ;
        RECT 0.100 1645.550 1587.025 1645.570 ;
        RECT 0.610 1644.730 1587.025 1645.550 ;
        RECT 0.100 1644.710 1587.025 1644.730 ;
        RECT 0.610 1643.890 1587.025 1644.710 ;
        RECT 0.100 1643.870 1587.025 1643.890 ;
        RECT 0.610 1643.050 1587.025 1643.870 ;
        RECT 0.100 1643.030 1587.025 1643.050 ;
        RECT 0.610 1642.210 1587.025 1643.030 ;
        RECT 0.100 1642.190 1587.025 1642.210 ;
        RECT 0.610 1641.370 1587.025 1642.190 ;
        RECT 0.100 1641.350 1587.025 1641.370 ;
        RECT 0.610 1640.530 1587.025 1641.350 ;
        RECT 0.100 1640.510 1587.025 1640.530 ;
        RECT 0.610 1639.690 1587.025 1640.510 ;
        RECT 0.100 1639.670 1587.025 1639.690 ;
        RECT 0.610 1638.850 1587.025 1639.670 ;
        RECT 0.100 1638.830 1587.025 1638.850 ;
        RECT 0.610 1638.010 1587.025 1638.830 ;
        RECT 0.100 1637.990 1587.025 1638.010 ;
        RECT 0.610 1637.170 1587.025 1637.990 ;
        RECT 0.100 1637.150 1587.025 1637.170 ;
        RECT 0.610 1636.330 1587.025 1637.150 ;
        RECT 0.100 1636.310 1587.025 1636.330 ;
        RECT 0.610 1635.490 1587.025 1636.310 ;
        RECT 0.100 1635.470 1587.025 1635.490 ;
        RECT 0.610 1634.650 1587.025 1635.470 ;
        RECT 0.100 1634.630 1587.025 1634.650 ;
        RECT 0.610 1633.810 1587.025 1634.630 ;
        RECT 0.100 1633.790 1587.025 1633.810 ;
        RECT 0.610 1632.970 1587.025 1633.790 ;
        RECT 0.100 1632.950 1587.025 1632.970 ;
        RECT 0.610 1632.130 1587.025 1632.950 ;
        RECT 0.100 1632.110 1587.025 1632.130 ;
        RECT 0.610 1631.290 1587.025 1632.110 ;
        RECT 0.100 1631.270 1587.025 1631.290 ;
        RECT 0.610 1630.450 1587.025 1631.270 ;
        RECT 0.100 1630.430 1587.025 1630.450 ;
        RECT 0.610 1629.610 1587.025 1630.430 ;
        RECT 0.100 1629.590 1587.025 1629.610 ;
        RECT 0.610 1628.770 1587.025 1629.590 ;
        RECT 0.100 1628.750 1587.025 1628.770 ;
        RECT 0.610 1627.930 1587.025 1628.750 ;
        RECT 0.100 1627.910 1587.025 1627.930 ;
        RECT 0.610 1627.090 1587.025 1627.910 ;
        RECT 0.100 1627.070 1587.025 1627.090 ;
        RECT 0.610 1626.250 1587.025 1627.070 ;
        RECT 0.100 1626.230 1587.025 1626.250 ;
        RECT 0.610 1625.410 1587.025 1626.230 ;
        RECT 0.100 1625.390 1587.025 1625.410 ;
        RECT 0.610 1624.570 1587.025 1625.390 ;
        RECT 0.100 1624.550 1587.025 1624.570 ;
        RECT 0.610 1623.730 1587.025 1624.550 ;
        RECT 0.100 1623.710 1587.025 1623.730 ;
        RECT 0.610 1622.890 1587.025 1623.710 ;
        RECT 0.100 1622.870 1587.025 1622.890 ;
        RECT 0.610 1622.050 1587.025 1622.870 ;
        RECT 0.100 1622.030 1587.025 1622.050 ;
        RECT 0.610 1621.210 1587.025 1622.030 ;
        RECT 0.100 1621.190 1587.025 1621.210 ;
        RECT 0.610 1620.370 1587.025 1621.190 ;
        RECT 0.100 1620.350 1587.025 1620.370 ;
        RECT 0.610 1619.530 1587.025 1620.350 ;
        RECT 0.100 1619.510 1587.025 1619.530 ;
        RECT 0.610 1618.690 1587.025 1619.510 ;
        RECT 0.100 1618.670 1587.025 1618.690 ;
        RECT 0.610 1617.850 1587.025 1618.670 ;
        RECT 0.100 1617.830 1587.025 1617.850 ;
        RECT 0.610 1617.010 1587.025 1617.830 ;
        RECT 0.100 1616.990 1587.025 1617.010 ;
        RECT 0.610 1616.170 1587.025 1616.990 ;
        RECT 0.100 1616.150 1587.025 1616.170 ;
        RECT 0.610 1615.330 1587.025 1616.150 ;
        RECT 0.100 1615.310 1587.025 1615.330 ;
        RECT 0.610 1614.490 1587.025 1615.310 ;
        RECT 0.100 1614.470 1587.025 1614.490 ;
        RECT 0.610 1613.650 1587.025 1614.470 ;
        RECT 0.100 1613.630 1587.025 1613.650 ;
        RECT 0.610 1612.810 1587.025 1613.630 ;
        RECT 0.100 1612.790 1587.025 1612.810 ;
        RECT 0.610 1611.970 1587.025 1612.790 ;
        RECT 0.100 1611.950 1587.025 1611.970 ;
        RECT 0.610 1611.130 1587.025 1611.950 ;
        RECT 0.100 1611.110 1587.025 1611.130 ;
        RECT 0.610 1610.290 1587.025 1611.110 ;
        RECT 0.100 1610.270 1587.025 1610.290 ;
        RECT 0.610 1609.450 1587.025 1610.270 ;
        RECT 0.100 1609.430 1587.025 1609.450 ;
        RECT 0.610 1608.610 1587.025 1609.430 ;
        RECT 0.100 1608.590 1587.025 1608.610 ;
        RECT 0.610 1607.770 1587.025 1608.590 ;
        RECT 0.100 1607.750 1587.025 1607.770 ;
        RECT 0.610 1606.930 1587.025 1607.750 ;
        RECT 0.100 1606.910 1587.025 1606.930 ;
        RECT 0.610 1606.090 1587.025 1606.910 ;
        RECT 0.100 1606.070 1587.025 1606.090 ;
        RECT 0.610 1605.250 1587.025 1606.070 ;
        RECT 0.100 1605.230 1587.025 1605.250 ;
        RECT 0.610 1604.410 1587.025 1605.230 ;
        RECT 0.100 1604.390 1587.025 1604.410 ;
        RECT 0.610 1603.570 1587.025 1604.390 ;
        RECT 0.100 1603.550 1587.025 1603.570 ;
        RECT 0.610 1602.730 1587.025 1603.550 ;
        RECT 0.100 1602.710 1587.025 1602.730 ;
        RECT 0.610 1601.890 1587.025 1602.710 ;
        RECT 0.100 1601.870 1587.025 1601.890 ;
        RECT 0.610 1601.050 1587.025 1601.870 ;
        RECT 0.100 1601.030 1587.025 1601.050 ;
        RECT 0.610 1600.210 1587.025 1601.030 ;
        RECT 0.100 1600.190 1587.025 1600.210 ;
        RECT 0.610 1599.370 1587.025 1600.190 ;
        RECT 0.100 1599.350 1587.025 1599.370 ;
        RECT 0.610 1598.530 1587.025 1599.350 ;
        RECT 0.100 1598.510 1587.025 1598.530 ;
        RECT 0.610 1597.690 1587.025 1598.510 ;
        RECT 0.100 1597.670 1587.025 1597.690 ;
        RECT 0.610 1596.850 1587.025 1597.670 ;
        RECT 0.100 1596.830 1587.025 1596.850 ;
        RECT 0.610 1596.010 1587.025 1596.830 ;
        RECT 0.100 1595.990 1587.025 1596.010 ;
        RECT 0.610 1595.170 1587.025 1595.990 ;
        RECT 0.100 1595.150 1587.025 1595.170 ;
        RECT 0.610 1594.330 1587.025 1595.150 ;
        RECT 0.100 1594.310 1587.025 1594.330 ;
        RECT 0.610 1593.490 1587.025 1594.310 ;
        RECT 0.100 1593.470 1587.025 1593.490 ;
        RECT 0.610 1592.650 1587.025 1593.470 ;
        RECT 0.100 1592.630 1587.025 1592.650 ;
        RECT 0.610 1591.810 1587.025 1592.630 ;
        RECT 0.100 1591.790 1587.025 1591.810 ;
        RECT 0.610 1590.970 1587.025 1591.790 ;
        RECT 0.100 1590.950 1587.025 1590.970 ;
        RECT 0.610 1590.130 1587.025 1590.950 ;
        RECT 0.100 1590.110 1587.025 1590.130 ;
        RECT 0.610 1589.290 1587.025 1590.110 ;
        RECT 0.100 1589.270 1587.025 1589.290 ;
        RECT 0.610 1588.450 1587.025 1589.270 ;
        RECT 0.100 1588.430 1587.025 1588.450 ;
        RECT 0.610 1587.610 1587.025 1588.430 ;
        RECT 0.100 1587.590 1587.025 1587.610 ;
        RECT 0.610 1586.770 1587.025 1587.590 ;
        RECT 0.100 1586.750 1587.025 1586.770 ;
        RECT 0.610 1585.930 1587.025 1586.750 ;
        RECT 0.100 1585.910 1587.025 1585.930 ;
        RECT 0.610 1585.090 1587.025 1585.910 ;
        RECT 0.100 1585.070 1587.025 1585.090 ;
        RECT 0.610 1584.250 1587.025 1585.070 ;
        RECT 0.100 1584.230 1587.025 1584.250 ;
        RECT 0.610 1583.410 1587.025 1584.230 ;
        RECT 0.100 1583.390 1587.025 1583.410 ;
        RECT 0.610 1582.570 1587.025 1583.390 ;
        RECT 0.100 1582.550 1587.025 1582.570 ;
        RECT 0.610 1581.730 1587.025 1582.550 ;
        RECT 0.100 1581.710 1587.025 1581.730 ;
        RECT 0.610 1580.890 1587.025 1581.710 ;
        RECT 0.100 1580.870 1587.025 1580.890 ;
        RECT 0.610 1580.050 1587.025 1580.870 ;
        RECT 0.100 1580.030 1587.025 1580.050 ;
        RECT 0.610 1579.210 1587.025 1580.030 ;
        RECT 0.100 1579.190 1587.025 1579.210 ;
        RECT 0.610 1578.370 1587.025 1579.190 ;
        RECT 0.100 1578.350 1587.025 1578.370 ;
        RECT 0.610 1577.530 1587.025 1578.350 ;
        RECT 0.100 1577.510 1587.025 1577.530 ;
        RECT 0.610 1576.690 1587.025 1577.510 ;
        RECT 0.100 1576.670 1587.025 1576.690 ;
        RECT 0.610 1575.850 1587.025 1576.670 ;
        RECT 0.100 1575.830 1587.025 1575.850 ;
        RECT 0.610 1575.010 1587.025 1575.830 ;
        RECT 0.100 1574.990 1587.025 1575.010 ;
        RECT 0.610 1574.170 1587.025 1574.990 ;
        RECT 0.100 1574.150 1587.025 1574.170 ;
        RECT 0.610 1573.330 1587.025 1574.150 ;
        RECT 0.100 1573.310 1587.025 1573.330 ;
        RECT 0.610 1572.490 1587.025 1573.310 ;
        RECT 0.100 1572.470 1587.025 1572.490 ;
        RECT 0.610 1571.650 1587.025 1572.470 ;
        RECT 0.100 1571.630 1587.025 1571.650 ;
        RECT 0.610 1570.810 1587.025 1571.630 ;
        RECT 0.100 1570.790 1587.025 1570.810 ;
        RECT 0.610 1569.970 1587.025 1570.790 ;
        RECT 0.100 1569.950 1587.025 1569.970 ;
        RECT 0.610 1569.130 1587.025 1569.950 ;
        RECT 0.100 1569.110 1587.025 1569.130 ;
        RECT 0.610 1568.290 1587.025 1569.110 ;
        RECT 0.100 1568.270 1587.025 1568.290 ;
        RECT 0.610 1567.450 1587.025 1568.270 ;
        RECT 0.100 1567.430 1587.025 1567.450 ;
        RECT 0.610 1566.610 1587.025 1567.430 ;
        RECT 0.100 1566.590 1587.025 1566.610 ;
        RECT 0.610 1565.770 1587.025 1566.590 ;
        RECT 0.100 1565.750 1587.025 1565.770 ;
        RECT 0.610 1564.930 1587.025 1565.750 ;
        RECT 0.100 1564.910 1587.025 1564.930 ;
        RECT 0.610 1564.090 1587.025 1564.910 ;
        RECT 0.100 1564.070 1587.025 1564.090 ;
        RECT 0.610 1563.250 1587.025 1564.070 ;
        RECT 0.100 1563.230 1587.025 1563.250 ;
        RECT 0.610 1562.410 1587.025 1563.230 ;
        RECT 0.100 1562.390 1587.025 1562.410 ;
        RECT 0.610 1561.570 1587.025 1562.390 ;
        RECT 0.100 1561.550 1587.025 1561.570 ;
        RECT 0.610 1560.730 1587.025 1561.550 ;
        RECT 0.100 1560.710 1587.025 1560.730 ;
        RECT 0.610 1559.890 1587.025 1560.710 ;
        RECT 0.100 1559.870 1587.025 1559.890 ;
        RECT 0.610 1559.050 1587.025 1559.870 ;
        RECT 0.100 1559.030 1587.025 1559.050 ;
        RECT 0.610 1558.210 1587.025 1559.030 ;
        RECT 0.100 1558.190 1587.025 1558.210 ;
        RECT 0.610 1557.370 1587.025 1558.190 ;
        RECT 0.100 1557.350 1587.025 1557.370 ;
        RECT 0.610 1556.530 1587.025 1557.350 ;
        RECT 0.100 1556.510 1587.025 1556.530 ;
        RECT 0.610 1555.690 1587.025 1556.510 ;
        RECT 0.100 1555.670 1587.025 1555.690 ;
        RECT 0.610 1554.850 1587.025 1555.670 ;
        RECT 0.100 1554.830 1587.025 1554.850 ;
        RECT 0.610 1554.010 1587.025 1554.830 ;
        RECT 0.100 1553.990 1587.025 1554.010 ;
        RECT 0.610 1553.170 1587.025 1553.990 ;
        RECT 0.100 1553.150 1587.025 1553.170 ;
        RECT 0.610 1552.330 1587.025 1553.150 ;
        RECT 0.100 1552.310 1587.025 1552.330 ;
        RECT 0.610 1551.490 1587.025 1552.310 ;
        RECT 0.100 1551.470 1587.025 1551.490 ;
        RECT 0.610 1550.650 1587.025 1551.470 ;
        RECT 0.100 1550.630 1587.025 1550.650 ;
        RECT 0.610 1549.810 1587.025 1550.630 ;
        RECT 0.100 1549.790 1587.025 1549.810 ;
        RECT 0.610 1548.970 1587.025 1549.790 ;
        RECT 0.100 1548.950 1587.025 1548.970 ;
        RECT 0.610 1548.130 1587.025 1548.950 ;
        RECT 0.100 1548.110 1587.025 1548.130 ;
        RECT 0.610 1547.290 1587.025 1548.110 ;
        RECT 0.100 1547.270 1587.025 1547.290 ;
        RECT 0.610 1546.450 1587.025 1547.270 ;
        RECT 0.100 1546.430 1587.025 1546.450 ;
        RECT 0.610 1545.610 1587.025 1546.430 ;
        RECT 0.100 1545.590 1587.025 1545.610 ;
        RECT 0.610 1544.770 1587.025 1545.590 ;
        RECT 0.100 1544.750 1587.025 1544.770 ;
        RECT 0.610 1543.930 1587.025 1544.750 ;
        RECT 0.100 1543.910 1587.025 1543.930 ;
        RECT 0.610 1543.090 1587.025 1543.910 ;
        RECT 0.100 1543.070 1587.025 1543.090 ;
        RECT 0.610 1542.250 1587.025 1543.070 ;
        RECT 0.100 1542.230 1587.025 1542.250 ;
        RECT 0.610 1541.410 1587.025 1542.230 ;
        RECT 0.100 1541.390 1587.025 1541.410 ;
        RECT 0.610 1540.570 1587.025 1541.390 ;
        RECT 0.100 1540.550 1587.025 1540.570 ;
        RECT 0.610 1539.730 1587.025 1540.550 ;
        RECT 0.100 1539.710 1587.025 1539.730 ;
        RECT 0.610 1538.890 1587.025 1539.710 ;
        RECT 0.100 1538.870 1587.025 1538.890 ;
        RECT 0.610 1538.050 1587.025 1538.870 ;
        RECT 0.100 1538.030 1587.025 1538.050 ;
        RECT 0.610 1537.210 1587.025 1538.030 ;
        RECT 0.100 1537.190 1587.025 1537.210 ;
        RECT 0.610 1536.370 1587.025 1537.190 ;
        RECT 0.100 1536.350 1587.025 1536.370 ;
        RECT 0.610 1535.530 1587.025 1536.350 ;
        RECT 0.100 1535.510 1587.025 1535.530 ;
        RECT 0.610 1534.690 1587.025 1535.510 ;
        RECT 0.100 1534.670 1587.025 1534.690 ;
        RECT 0.610 1533.850 1587.025 1534.670 ;
        RECT 0.100 1533.830 1587.025 1533.850 ;
        RECT 0.610 1533.010 1587.025 1533.830 ;
        RECT 0.100 1532.990 1587.025 1533.010 ;
        RECT 0.610 1532.170 1587.025 1532.990 ;
        RECT 0.100 1532.150 1587.025 1532.170 ;
        RECT 0.610 1531.330 1587.025 1532.150 ;
        RECT 0.100 1531.310 1587.025 1531.330 ;
        RECT 0.610 1530.490 1587.025 1531.310 ;
        RECT 0.100 1530.470 1587.025 1530.490 ;
        RECT 0.610 1529.650 1587.025 1530.470 ;
        RECT 0.100 1529.630 1587.025 1529.650 ;
        RECT 0.610 1528.810 1587.025 1529.630 ;
        RECT 0.100 1528.790 1587.025 1528.810 ;
        RECT 0.610 1527.970 1587.025 1528.790 ;
        RECT 0.100 1527.950 1587.025 1527.970 ;
        RECT 0.610 1527.130 1587.025 1527.950 ;
        RECT 0.100 1527.110 1587.025 1527.130 ;
        RECT 0.610 1526.290 1587.025 1527.110 ;
        RECT 0.100 1526.270 1587.025 1526.290 ;
        RECT 0.610 1525.450 1587.025 1526.270 ;
        RECT 0.100 1525.430 1587.025 1525.450 ;
        RECT 0.610 1524.610 1587.025 1525.430 ;
        RECT 0.100 1524.590 1587.025 1524.610 ;
        RECT 0.610 1523.770 1587.025 1524.590 ;
        RECT 0.100 1523.750 1587.025 1523.770 ;
        RECT 0.610 1522.930 1587.025 1523.750 ;
        RECT 0.100 1522.910 1587.025 1522.930 ;
        RECT 0.610 1522.090 1587.025 1522.910 ;
        RECT 0.100 1522.070 1587.025 1522.090 ;
        RECT 0.610 1521.250 1587.025 1522.070 ;
        RECT 0.100 1521.230 1587.025 1521.250 ;
        RECT 0.610 1520.410 1587.025 1521.230 ;
        RECT 0.100 1520.390 1587.025 1520.410 ;
        RECT 0.610 1519.570 1587.025 1520.390 ;
        RECT 0.100 1519.550 1587.025 1519.570 ;
        RECT 0.610 1518.730 1587.025 1519.550 ;
        RECT 0.100 1518.710 1587.025 1518.730 ;
        RECT 0.610 1517.890 1587.025 1518.710 ;
        RECT 0.100 1517.870 1587.025 1517.890 ;
        RECT 0.610 1517.050 1587.025 1517.870 ;
        RECT 0.100 1517.030 1587.025 1517.050 ;
        RECT 0.610 1516.210 1587.025 1517.030 ;
        RECT 0.100 1516.190 1587.025 1516.210 ;
        RECT 0.610 1515.370 1587.025 1516.190 ;
        RECT 0.100 1515.350 1587.025 1515.370 ;
        RECT 0.610 1514.530 1587.025 1515.350 ;
        RECT 0.100 1514.510 1587.025 1514.530 ;
        RECT 0.610 1513.690 1587.025 1514.510 ;
        RECT 0.100 1513.670 1587.025 1513.690 ;
        RECT 0.610 1512.850 1587.025 1513.670 ;
        RECT 0.100 1512.830 1587.025 1512.850 ;
        RECT 0.610 1512.010 1587.025 1512.830 ;
        RECT 0.100 1511.990 1587.025 1512.010 ;
        RECT 0.610 1511.170 1587.025 1511.990 ;
        RECT 0.100 1511.150 1587.025 1511.170 ;
        RECT 0.610 1510.330 1587.025 1511.150 ;
        RECT 0.100 1510.310 1587.025 1510.330 ;
        RECT 0.610 1509.490 1587.025 1510.310 ;
        RECT 0.100 1509.470 1587.025 1509.490 ;
        RECT 0.610 1508.650 1587.025 1509.470 ;
        RECT 0.100 1508.630 1587.025 1508.650 ;
        RECT 0.610 1507.810 1587.025 1508.630 ;
        RECT 0.100 1507.790 1587.025 1507.810 ;
        RECT 0.610 1506.970 1587.025 1507.790 ;
        RECT 0.100 1506.950 1587.025 1506.970 ;
        RECT 0.610 1506.130 1587.025 1506.950 ;
        RECT 0.100 1506.110 1587.025 1506.130 ;
        RECT 0.610 1505.290 1587.025 1506.110 ;
        RECT 0.100 1505.270 1587.025 1505.290 ;
        RECT 0.610 1504.450 1587.025 1505.270 ;
        RECT 0.100 1504.430 1587.025 1504.450 ;
        RECT 0.610 1503.610 1587.025 1504.430 ;
        RECT 0.100 1503.590 1587.025 1503.610 ;
        RECT 0.610 1502.770 1587.025 1503.590 ;
        RECT 0.100 1502.750 1587.025 1502.770 ;
        RECT 0.610 1501.930 1587.025 1502.750 ;
        RECT 0.100 1501.910 1587.025 1501.930 ;
        RECT 0.610 1501.090 1587.025 1501.910 ;
        RECT 0.100 1501.070 1587.025 1501.090 ;
        RECT 0.610 1500.250 1587.025 1501.070 ;
        RECT 0.100 1500.230 1587.025 1500.250 ;
        RECT 0.610 1499.410 1587.025 1500.230 ;
        RECT 0.100 1499.390 1587.025 1499.410 ;
        RECT 0.610 1498.570 1587.025 1499.390 ;
        RECT 0.100 1498.550 1587.025 1498.570 ;
        RECT 0.610 1497.730 1587.025 1498.550 ;
        RECT 0.100 1497.710 1587.025 1497.730 ;
        RECT 0.610 1496.890 1587.025 1497.710 ;
        RECT 0.100 1496.870 1587.025 1496.890 ;
        RECT 0.610 1496.050 1587.025 1496.870 ;
        RECT 0.100 1496.030 1587.025 1496.050 ;
        RECT 0.610 1495.210 1587.025 1496.030 ;
        RECT 0.100 1495.190 1587.025 1495.210 ;
        RECT 0.610 1494.370 1587.025 1495.190 ;
        RECT 0.100 1494.350 1587.025 1494.370 ;
        RECT 0.610 1493.530 1587.025 1494.350 ;
        RECT 0.100 1493.510 1587.025 1493.530 ;
        RECT 0.610 1492.690 1587.025 1493.510 ;
        RECT 0.100 1492.670 1587.025 1492.690 ;
        RECT 0.610 1491.850 1587.025 1492.670 ;
        RECT 0.100 1485.950 1587.025 1491.850 ;
        RECT 0.610 1485.130 1587.025 1485.950 ;
        RECT 0.100 1223.030 1587.025 1485.130 ;
        RECT 0.610 1222.210 1587.025 1223.030 ;
        RECT 0.100 1149.950 1587.025 1222.210 ;
        RECT 0.610 1149.130 1587.025 1149.950 ;
        RECT 0.100 1149.110 1587.025 1149.130 ;
        RECT 0.610 1148.290 1587.025 1149.110 ;
        RECT 0.100 1148.270 1587.025 1148.290 ;
        RECT 0.610 1147.450 1587.025 1148.270 ;
        RECT 0.100 1147.430 1587.025 1147.450 ;
        RECT 0.610 1146.610 1587.025 1147.430 ;
        RECT 0.100 1146.590 1587.025 1146.610 ;
        RECT 0.610 1145.770 1587.025 1146.590 ;
        RECT 0.100 1145.750 1587.025 1145.770 ;
        RECT 0.610 1144.930 1587.025 1145.750 ;
        RECT 0.100 1144.910 1587.025 1144.930 ;
        RECT 0.610 1144.090 1587.025 1144.910 ;
        RECT 0.100 1144.070 1587.025 1144.090 ;
        RECT 0.610 1143.250 1587.025 1144.070 ;
        RECT 0.100 1143.230 1587.025 1143.250 ;
        RECT 0.610 1142.410 1587.025 1143.230 ;
        RECT 0.100 1142.390 1587.025 1142.410 ;
        RECT 0.610 1141.570 1587.025 1142.390 ;
        RECT 0.100 1141.550 1587.025 1141.570 ;
        RECT 0.610 1140.730 1587.025 1141.550 ;
        RECT 0.100 1140.710 1587.025 1140.730 ;
        RECT 0.610 1139.890 1587.025 1140.710 ;
        RECT 0.100 1139.870 1587.025 1139.890 ;
        RECT 0.610 1139.050 1587.025 1139.870 ;
        RECT 0.100 1139.030 1587.025 1139.050 ;
        RECT 0.610 1138.210 1587.025 1139.030 ;
        RECT 0.100 1138.190 1587.025 1138.210 ;
        RECT 0.610 1137.370 1587.025 1138.190 ;
        RECT 0.100 1137.350 1587.025 1137.370 ;
        RECT 0.610 1136.530 1587.025 1137.350 ;
        RECT 0.100 1136.510 1587.025 1136.530 ;
        RECT 0.610 1135.690 1587.025 1136.510 ;
        RECT 0.100 1135.670 1587.025 1135.690 ;
        RECT 0.610 1134.850 1587.025 1135.670 ;
        RECT 0.100 1134.830 1587.025 1134.850 ;
        RECT 0.610 1134.010 1587.025 1134.830 ;
        RECT 0.100 1133.990 1587.025 1134.010 ;
        RECT 0.610 1133.170 1587.025 1133.990 ;
        RECT 0.100 1133.150 1587.025 1133.170 ;
        RECT 0.610 1132.330 1587.025 1133.150 ;
        RECT 0.100 1132.310 1587.025 1132.330 ;
        RECT 0.610 1131.490 1587.025 1132.310 ;
        RECT 0.100 1131.470 1587.025 1131.490 ;
        RECT 0.610 1130.650 1587.025 1131.470 ;
        RECT 0.100 1130.630 1587.025 1130.650 ;
        RECT 0.610 1129.810 1587.025 1130.630 ;
        RECT 0.100 1129.790 1587.025 1129.810 ;
        RECT 0.610 1128.970 1587.025 1129.790 ;
        RECT 0.100 1128.950 1587.025 1128.970 ;
        RECT 0.610 1128.130 1587.025 1128.950 ;
        RECT 0.100 1128.110 1587.025 1128.130 ;
        RECT 0.610 1127.290 1587.025 1128.110 ;
        RECT 0.100 1127.270 1587.025 1127.290 ;
        RECT 0.610 1126.450 1587.025 1127.270 ;
        RECT 0.100 1126.430 1587.025 1126.450 ;
        RECT 0.610 1125.610 1587.025 1126.430 ;
        RECT 0.100 1125.590 1587.025 1125.610 ;
        RECT 0.610 1124.770 1587.025 1125.590 ;
        RECT 0.100 1124.750 1587.025 1124.770 ;
        RECT 0.610 1123.930 1587.025 1124.750 ;
        RECT 0.100 1123.910 1587.025 1123.930 ;
        RECT 0.610 1123.090 1587.025 1123.910 ;
        RECT 0.100 1123.070 1587.025 1123.090 ;
        RECT 0.610 1122.250 1587.025 1123.070 ;
        RECT 0.100 1122.230 1587.025 1122.250 ;
        RECT 0.610 1121.410 1587.025 1122.230 ;
        RECT 0.100 1121.390 1587.025 1121.410 ;
        RECT 0.610 1120.570 1587.025 1121.390 ;
        RECT 0.100 1120.550 1587.025 1120.570 ;
        RECT 0.610 1119.730 1587.025 1120.550 ;
        RECT 0.100 1119.710 1587.025 1119.730 ;
        RECT 0.610 1118.890 1587.025 1119.710 ;
        RECT 0.100 1118.870 1587.025 1118.890 ;
        RECT 0.610 1118.050 1587.025 1118.870 ;
        RECT 0.100 1118.030 1587.025 1118.050 ;
        RECT 0.610 1117.210 1587.025 1118.030 ;
        RECT 0.100 1117.190 1587.025 1117.210 ;
        RECT 0.610 1116.370 1587.025 1117.190 ;
        RECT 0.100 1116.350 1587.025 1116.370 ;
        RECT 0.610 1115.530 1587.025 1116.350 ;
        RECT 0.100 1115.510 1587.025 1115.530 ;
        RECT 0.610 1114.690 1587.025 1115.510 ;
        RECT 0.100 1114.670 1587.025 1114.690 ;
        RECT 0.610 1113.850 1587.025 1114.670 ;
        RECT 0.100 1113.830 1587.025 1113.850 ;
        RECT 0.610 1113.010 1587.025 1113.830 ;
        RECT 0.100 1112.990 1587.025 1113.010 ;
        RECT 0.610 1112.170 1587.025 1112.990 ;
        RECT 0.100 1112.150 1587.025 1112.170 ;
        RECT 0.610 1111.330 1587.025 1112.150 ;
        RECT 0.100 1111.310 1587.025 1111.330 ;
        RECT 0.610 1110.490 1587.025 1111.310 ;
        RECT 0.100 1110.470 1587.025 1110.490 ;
        RECT 0.610 1109.650 1587.025 1110.470 ;
        RECT 0.100 1109.630 1587.025 1109.650 ;
        RECT 0.610 1108.810 1587.025 1109.630 ;
        RECT 0.100 1108.790 1587.025 1108.810 ;
        RECT 0.610 1107.970 1587.025 1108.790 ;
        RECT 0.100 1107.950 1587.025 1107.970 ;
        RECT 0.610 1107.130 1587.025 1107.950 ;
        RECT 0.100 1107.110 1587.025 1107.130 ;
        RECT 0.610 1106.290 1587.025 1107.110 ;
        RECT 0.100 1106.270 1587.025 1106.290 ;
        RECT 0.610 1105.450 1587.025 1106.270 ;
        RECT 0.100 1105.430 1587.025 1105.450 ;
        RECT 0.610 1104.610 1587.025 1105.430 ;
        RECT 0.100 1104.590 1587.025 1104.610 ;
        RECT 0.610 1103.770 1587.025 1104.590 ;
        RECT 0.100 1103.750 1587.025 1103.770 ;
        RECT 0.610 1102.930 1587.025 1103.750 ;
        RECT 0.100 1102.910 1587.025 1102.930 ;
        RECT 0.610 1102.090 1587.025 1102.910 ;
        RECT 0.100 1102.070 1587.025 1102.090 ;
        RECT 0.610 1101.250 1587.025 1102.070 ;
        RECT 0.100 1101.230 1587.025 1101.250 ;
        RECT 0.610 1100.410 1587.025 1101.230 ;
        RECT 0.100 1100.390 1587.025 1100.410 ;
        RECT 0.610 1099.570 1587.025 1100.390 ;
        RECT 0.100 1099.550 1587.025 1099.570 ;
        RECT 0.610 1098.730 1587.025 1099.550 ;
        RECT 0.100 1098.710 1587.025 1098.730 ;
        RECT 0.610 1097.890 1587.025 1098.710 ;
        RECT 0.100 1097.870 1587.025 1097.890 ;
        RECT 0.610 1097.050 1587.025 1097.870 ;
        RECT 0.100 1097.030 1587.025 1097.050 ;
        RECT 0.610 1096.210 1587.025 1097.030 ;
        RECT 0.100 1096.190 1587.025 1096.210 ;
        RECT 0.610 1095.370 1587.025 1096.190 ;
        RECT 0.100 1095.350 1587.025 1095.370 ;
        RECT 0.610 1094.530 1587.025 1095.350 ;
        RECT 0.100 1094.510 1587.025 1094.530 ;
        RECT 0.610 1093.690 1587.025 1094.510 ;
        RECT 0.100 1093.670 1587.025 1093.690 ;
        RECT 0.610 1092.850 1587.025 1093.670 ;
        RECT 0.100 1092.830 1587.025 1092.850 ;
        RECT 0.610 1092.010 1587.025 1092.830 ;
        RECT 0.100 1091.990 1587.025 1092.010 ;
        RECT 0.610 1091.170 1587.025 1091.990 ;
        RECT 0.100 1091.150 1587.025 1091.170 ;
        RECT 0.610 1090.330 1587.025 1091.150 ;
        RECT 0.100 1090.310 1587.025 1090.330 ;
        RECT 0.610 1089.490 1587.025 1090.310 ;
        RECT 0.100 1089.470 1587.025 1089.490 ;
        RECT 0.610 1088.650 1587.025 1089.470 ;
        RECT 0.100 1088.630 1587.025 1088.650 ;
        RECT 0.610 1087.810 1587.025 1088.630 ;
        RECT 0.100 1087.790 1587.025 1087.810 ;
        RECT 0.610 1086.970 1587.025 1087.790 ;
        RECT 0.100 1086.950 1587.025 1086.970 ;
        RECT 0.610 1086.130 1587.025 1086.950 ;
        RECT 0.100 1086.110 1587.025 1086.130 ;
        RECT 0.610 1085.290 1587.025 1086.110 ;
        RECT 0.100 1085.270 1587.025 1085.290 ;
        RECT 0.610 1084.450 1587.025 1085.270 ;
        RECT 0.100 1084.430 1587.025 1084.450 ;
        RECT 0.610 1083.610 1587.025 1084.430 ;
        RECT 0.100 1083.590 1587.025 1083.610 ;
        RECT 0.610 1082.770 1587.025 1083.590 ;
        RECT 0.100 1082.750 1587.025 1082.770 ;
        RECT 0.610 1081.930 1587.025 1082.750 ;
        RECT 0.100 1081.910 1587.025 1081.930 ;
        RECT 0.610 1081.090 1587.025 1081.910 ;
        RECT 0.100 1081.070 1587.025 1081.090 ;
        RECT 0.610 1080.250 1587.025 1081.070 ;
        RECT 0.100 1080.230 1587.025 1080.250 ;
        RECT 0.610 1079.410 1587.025 1080.230 ;
        RECT 0.100 1079.390 1587.025 1079.410 ;
        RECT 0.610 1078.570 1587.025 1079.390 ;
        RECT 0.100 1078.550 1587.025 1078.570 ;
        RECT 0.610 1077.730 1587.025 1078.550 ;
        RECT 0.100 1077.710 1587.025 1077.730 ;
        RECT 0.610 1076.890 1587.025 1077.710 ;
        RECT 0.100 1076.870 1587.025 1076.890 ;
        RECT 0.610 1076.050 1587.025 1076.870 ;
        RECT 0.100 1076.030 1587.025 1076.050 ;
        RECT 0.610 1075.210 1587.025 1076.030 ;
        RECT 0.100 1075.190 1587.025 1075.210 ;
        RECT 0.610 1074.370 1587.025 1075.190 ;
        RECT 0.100 1074.350 1587.025 1074.370 ;
        RECT 0.610 1073.530 1587.025 1074.350 ;
        RECT 0.100 1073.510 1587.025 1073.530 ;
        RECT 0.610 1072.690 1587.025 1073.510 ;
        RECT 0.100 1072.670 1587.025 1072.690 ;
        RECT 0.610 1071.850 1587.025 1072.670 ;
        RECT 0.100 1071.830 1587.025 1071.850 ;
        RECT 0.610 1071.010 1587.025 1071.830 ;
        RECT 0.100 1070.990 1587.025 1071.010 ;
        RECT 0.610 1070.170 1587.025 1070.990 ;
        RECT 0.100 1070.150 1587.025 1070.170 ;
        RECT 0.610 1069.330 1587.025 1070.150 ;
        RECT 0.100 1059.230 1587.025 1069.330 ;
        RECT 0.610 1058.410 1587.025 1059.230 ;
        RECT 0.100 1015.550 1587.025 1058.410 ;
        RECT 0.610 1014.730 1587.025 1015.550 ;
        RECT 0.100 950.870 1587.025 1014.730 ;
        RECT 0.610 950.050 1587.025 950.870 ;
        RECT 0.100 68.780 1587.025 950.050 ;
      LAYER Metal4 ;
        RECT 0.375 78.815 1586.980 1706.605 ;
      LAYER Metal5 ;
        RECT 0.335 78.860 1585.585 1706.560 ;
      LAYER TopMetal1 ;
        RECT 0.690 88.640 61.260 1646.950 ;
        RECT 66.740 88.640 67.460 1646.950 ;
        RECT 72.940 88.640 136.860 1646.950 ;
        RECT 142.340 88.640 143.060 1646.950 ;
        RECT 148.540 88.640 212.460 1646.950 ;
        RECT 217.940 88.640 218.660 1646.950 ;
        RECT 224.140 88.640 288.060 1646.950 ;
        RECT 293.540 88.640 294.260 1646.950 ;
        RECT 299.740 506.460 363.660 1646.950 ;
        RECT 369.140 506.460 369.860 1646.950 ;
        RECT 375.340 506.460 439.260 1646.950 ;
        RECT 444.740 506.460 445.460 1646.950 ;
        RECT 450.940 1643.300 514.860 1646.950 ;
        RECT 520.340 1643.710 521.060 1646.950 ;
        RECT 526.540 1643.710 590.460 1646.950 ;
        RECT 520.340 1643.300 590.460 1643.710 ;
        RECT 595.940 1643.710 596.660 1646.950 ;
        RECT 602.140 1643.710 666.060 1646.950 ;
        RECT 595.940 1643.300 666.060 1643.710 ;
        RECT 671.540 1643.300 672.260 1646.950 ;
        RECT 677.740 1643.300 741.660 1646.950 ;
        RECT 450.940 1453.260 741.660 1643.300 ;
        RECT 450.940 1150.240 514.860 1453.260 ;
        RECT 520.340 1452.850 590.460 1453.260 ;
        RECT 520.340 1150.240 521.060 1452.850 ;
        RECT 526.540 1150.240 590.460 1452.850 ;
        RECT 595.940 1452.850 666.060 1453.260 ;
        RECT 595.940 1150.240 596.660 1452.850 ;
        RECT 602.140 1150.240 666.060 1452.850 ;
        RECT 671.540 1150.240 672.260 1453.260 ;
        RECT 677.740 1150.240 741.660 1453.260 ;
        RECT 450.940 953.260 741.660 1150.240 ;
        RECT 450.940 506.460 514.860 953.260 ;
        RECT 520.340 952.850 590.460 953.260 ;
        RECT 520.340 506.460 521.060 952.850 ;
        RECT 526.540 506.460 590.460 952.850 ;
        RECT 595.940 952.850 666.060 953.260 ;
        RECT 595.940 506.460 596.660 952.850 ;
        RECT 602.140 506.460 666.060 952.850 ;
        RECT 299.740 391.580 666.060 506.460 ;
        RECT 299.740 88.640 363.660 391.580 ;
        RECT 369.140 88.640 369.860 391.580 ;
        RECT 375.340 88.640 439.260 391.580 ;
        RECT 444.740 88.640 445.460 391.580 ;
        RECT 450.940 88.640 514.860 391.580 ;
        RECT 520.340 88.640 521.060 391.580 ;
        RECT 526.540 88.640 590.460 391.580 ;
        RECT 595.940 88.640 596.660 391.580 ;
        RECT 602.140 88.640 666.060 391.580 ;
        RECT 671.540 88.640 672.260 953.260 ;
        RECT 677.740 88.640 741.660 953.260 ;
        RECT 747.140 88.640 747.860 1646.950 ;
        RECT 753.340 88.640 817.260 1646.950 ;
        RECT 822.740 88.640 823.460 1646.950 ;
        RECT 828.940 88.640 892.860 1646.950 ;
        RECT 898.340 88.640 899.060 1646.950 ;
        RECT 904.540 88.640 968.460 1646.950 ;
        RECT 973.940 88.640 974.660 1646.950 ;
        RECT 980.140 88.640 1044.060 1646.950 ;
        RECT 1049.540 88.640 1050.260 1646.950 ;
        RECT 1055.740 88.640 1119.660 1646.950 ;
        RECT 1125.140 88.640 1125.860 1646.950 ;
        RECT 1131.340 88.640 1195.260 1646.950 ;
        RECT 1200.740 88.640 1201.460 1646.950 ;
        RECT 1206.940 88.640 1270.860 1646.950 ;
        RECT 1276.340 88.640 1277.060 1646.950 ;
        RECT 1282.540 88.640 1346.460 1646.950 ;
        RECT 1351.940 88.640 1352.660 1646.950 ;
        RECT 1358.140 88.640 1422.060 1646.950 ;
        RECT 1427.540 88.640 1428.260 1646.950 ;
        RECT 1433.740 88.640 1497.660 1646.950 ;
        RECT 1503.140 88.640 1503.860 1646.950 ;
        RECT 1509.340 88.640 1570.300 1646.950 ;
      LAYER TopMetal2 ;
        RECT 0.640 1587.820 1559.040 1647.000 ;
        RECT 0.640 1575.420 48.400 1587.820 ;
        RECT 0.640 1512.220 1559.040 1575.420 ;
        RECT 0.640 1499.820 48.400 1512.220 ;
        RECT 0.640 1436.620 1559.040 1499.820 ;
        RECT 0.640 1424.220 48.400 1436.620 ;
        RECT 0.640 1361.020 1559.040 1424.220 ;
        RECT 0.640 1348.620 48.400 1361.020 ;
        RECT 0.640 1285.420 1559.040 1348.620 ;
        RECT 0.640 1273.020 48.400 1285.420 ;
        RECT 0.640 1209.820 1559.040 1273.020 ;
        RECT 0.640 1197.420 48.400 1209.820 ;
        RECT 93.760 1197.420 360.640 1209.820 ;
        RECT 0.640 1134.220 1559.040 1197.420 ;
        RECT 0.640 1121.820 48.400 1134.220 ;
        RECT 93.760 1121.820 360.640 1134.220 ;
        RECT 843.760 1121.820 1034.320 1134.220 ;
        RECT 0.640 1058.620 1559.040 1121.820 ;
        RECT 0.640 1046.220 48.400 1058.620 ;
        RECT 93.760 1046.220 360.640 1058.620 ;
        RECT 493.760 1046.220 683.660 1058.620 ;
        RECT 843.760 1046.220 1034.320 1058.620 ;
        RECT 0.640 983.020 1559.040 1046.220 ;
        RECT 0.640 970.620 48.400 983.020 ;
        RECT 93.760 970.620 360.640 983.020 ;
        RECT 493.760 970.620 683.660 983.020 ;
        RECT 843.760 970.620 1034.320 983.020 ;
        RECT 0.640 907.420 1559.040 970.620 ;
        RECT 0.640 895.020 48.400 907.420 ;
        RECT 0.640 831.820 1559.040 895.020 ;
        RECT 0.640 819.420 48.400 831.820 ;
        RECT 0.640 756.220 1559.040 819.420 ;
        RECT 0.640 743.820 48.400 756.220 ;
        RECT 0.640 680.620 1559.040 743.820 ;
        RECT 0.640 668.220 48.400 680.620 ;
        RECT 0.640 605.020 1559.040 668.220 ;
        RECT 0.640 592.620 48.400 605.020 ;
        RECT 0.640 529.420 1559.040 592.620 ;
        RECT 0.640 517.020 48.400 529.420 ;
        RECT 0.640 453.820 1559.040 517.020 ;
        RECT 0.640 441.420 48.400 453.820 ;
        RECT 0.640 378.220 1559.040 441.420 ;
        RECT 0.640 365.820 48.400 378.220 ;
        RECT 0.640 302.620 1559.040 365.820 ;
        RECT 0.640 290.220 48.400 302.620 ;
        RECT 0.640 227.020 1559.040 290.220 ;
        RECT 0.640 214.620 48.400 227.020 ;
        RECT 0.640 151.420 1559.040 214.620 ;
        RECT 0.640 139.020 48.400 151.420 ;
        RECT 0.640 127.620 1559.040 139.020 ;
  END
END soc_top
END LIBRARY

